VERSION 5.8 ;
BUSBITCHARS "[]" ;
DIVIDERCHAR "/" ;
UNITS
    DATABASE MICRONS 1000 ;
END UNITS

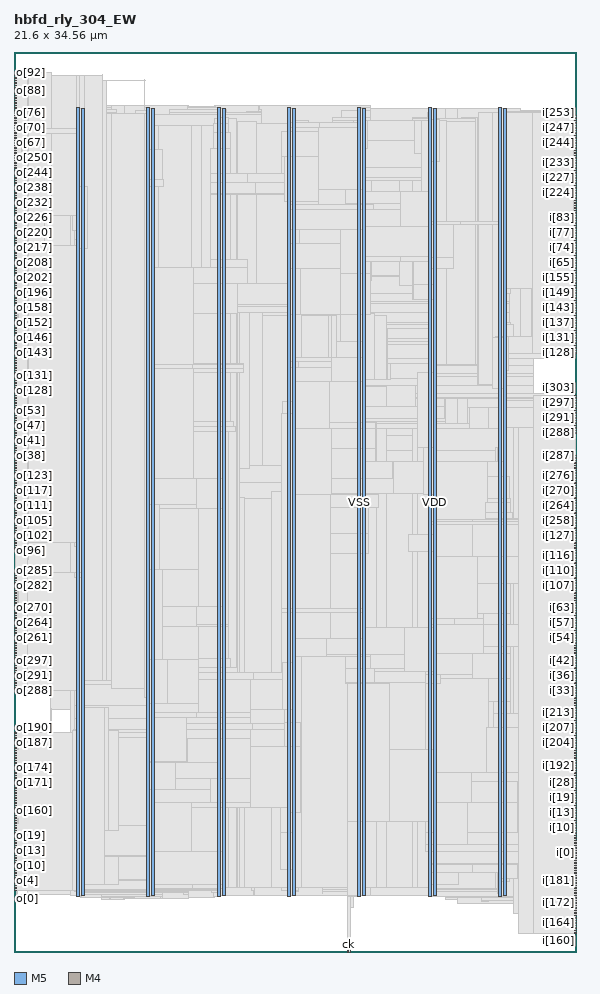
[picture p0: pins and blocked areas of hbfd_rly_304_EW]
MACRO hbfd_rly_304_EW
  FOREIGN hbfd_rly_304_EW 0 0 ;
  CLASS BLOCK ;
  SIZE 21.6 BY 34.56 ;
  PIN ck
    DIRECTION INPUT ;
    USE SIGNAL ;
    PORT
      LAYER M5 ;
        RECT  12.816 0 12.84 0.084 ;
    END
  END ck
  PIN i[0]
    DIRECTION INPUT ;
    USE SIGNAL ;
    PORT
      LAYER M4 ;
        RECT  21.516 3.792 21.6 3.816 ;
    END
  END i[0]
  PIN i[100]
    DIRECTION INPUT ;
    USE SIGNAL ;
    PORT
      LAYER M4 ;
        RECT  21.516 13.392 21.6 13.416 ;
    END
  END i[100]
  PIN i[101]
    DIRECTION INPUT ;
    USE SIGNAL ;
    PORT
      LAYER M4 ;
        RECT  21.516 13.488 21.6 13.512 ;
    END
  END i[101]
  PIN i[102]
    DIRECTION INPUT ;
    USE SIGNAL ;
    PORT
      LAYER M4 ;
        RECT  21.516 13.584 21.6 13.608 ;
    END
  END i[102]
  PIN i[103]
    DIRECTION INPUT ;
    USE SIGNAL ;
    PORT
      LAYER M4 ;
        RECT  21.516 13.68 21.6 13.704 ;
    END
  END i[103]
  PIN i[104]
    DIRECTION INPUT ;
    USE SIGNAL ;
    PORT
      LAYER M4 ;
        RECT  21.516 13.776 21.6 13.8 ;
    END
  END i[104]
  PIN i[105]
    DIRECTION INPUT ;
    USE SIGNAL ;
    PORT
      LAYER M4 ;
        RECT  21.516 13.872 21.6 13.896 ;
    END
  END i[105]
  PIN i[106]
    DIRECTION INPUT ;
    USE SIGNAL ;
    PORT
      LAYER M4 ;
        RECT  21.516 13.968 21.6 13.992 ;
    END
  END i[106]
  PIN i[107]
    DIRECTION INPUT ;
    USE SIGNAL ;
    PORT
      LAYER M4 ;
        RECT  21.516 14.064 21.6 14.088 ;
    END
  END i[107]
  PIN i[108]
    DIRECTION INPUT ;
    USE SIGNAL ;
    PORT
      LAYER M4 ;
        RECT  21.516 14.16 21.6 14.184 ;
    END
  END i[108]
  PIN i[109]
    DIRECTION INPUT ;
    USE SIGNAL ;
    PORT
      LAYER M4 ;
        RECT  21.516 14.256 21.6 14.28 ;
    END
  END i[109]
  PIN i[10]
    DIRECTION INPUT ;
    USE SIGNAL ;
    PORT
      LAYER M4 ;
        RECT  21.516 4.752 21.6 4.776 ;
    END
  END i[10]
  PIN i[110]
    DIRECTION INPUT ;
    USE SIGNAL ;
    PORT
      LAYER M4 ;
        RECT  21.516 14.352 21.6 14.376 ;
    END
  END i[110]
  PIN i[111]
    DIRECTION INPUT ;
    USE SIGNAL ;
    PORT
      LAYER M4 ;
        RECT  21.516 14.448 21.6 14.472 ;
    END
  END i[111]
  PIN i[112]
    DIRECTION INPUT ;
    USE SIGNAL ;
    PORT
      LAYER M4 ;
        RECT  21.516 14.544 21.6 14.568 ;
    END
  END i[112]
  PIN i[113]
    DIRECTION INPUT ;
    USE SIGNAL ;
    PORT
      LAYER M4 ;
        RECT  21.516 14.64 21.6 14.664 ;
    END
  END i[113]
  PIN i[114]
    DIRECTION INPUT ;
    USE SIGNAL ;
    PORT
      LAYER M4 ;
        RECT  21.516 14.736 21.6 14.76 ;
    END
  END i[114]
  PIN i[115]
    DIRECTION INPUT ;
    USE SIGNAL ;
    PORT
      LAYER M4 ;
        RECT  21.516 14.832 21.6 14.856 ;
    END
  END i[115]
  PIN i[116]
    DIRECTION INPUT ;
    USE SIGNAL ;
    PORT
      LAYER M4 ;
        RECT  21.516 14.928 21.6 14.952 ;
    END
  END i[116]
  PIN i[117]
    DIRECTION INPUT ;
    USE SIGNAL ;
    PORT
      LAYER M4 ;
        RECT  21.516 15.024 21.6 15.048 ;
    END
  END i[117]
  PIN i[118]
    DIRECTION INPUT ;
    USE SIGNAL ;
    PORT
      LAYER M4 ;
        RECT  21.516 15.12 21.6 15.144 ;
    END
  END i[118]
  PIN i[119]
    DIRECTION INPUT ;
    USE SIGNAL ;
    PORT
      LAYER M4 ;
        RECT  21.516 15.216 21.6 15.24 ;
    END
  END i[119]
  PIN i[11]
    DIRECTION INPUT ;
    USE SIGNAL ;
    PORT
      LAYER M4 ;
        RECT  21.516 4.848 21.6 4.872 ;
    END
  END i[11]
  PIN i[120]
    DIRECTION INPUT ;
    USE SIGNAL ;
    PORT
      LAYER M4 ;
        RECT  21.516 15.312 21.6 15.336 ;
    END
  END i[120]
  PIN i[121]
    DIRECTION INPUT ;
    USE SIGNAL ;
    PORT
      LAYER M4 ;
        RECT  21.516 15.408 21.6 15.432 ;
    END
  END i[121]
  PIN i[122]
    DIRECTION INPUT ;
    USE SIGNAL ;
    PORT
      LAYER M4 ;
        RECT  21.516 15.504 21.6 15.528 ;
    END
  END i[122]
  PIN i[123]
    DIRECTION INPUT ;
    USE SIGNAL ;
    PORT
      LAYER M4 ;
        RECT  21.516 15.6 21.6 15.624 ;
    END
  END i[123]
  PIN i[124]
    DIRECTION INPUT ;
    USE SIGNAL ;
    PORT
      LAYER M4 ;
        RECT  21.516 15.696 21.6 15.72 ;
    END
  END i[124]
  PIN i[125]
    DIRECTION INPUT ;
    USE SIGNAL ;
    PORT
      LAYER M4 ;
        RECT  21.516 15.792 21.6 15.816 ;
    END
  END i[125]
  PIN i[126]
    DIRECTION INPUT ;
    USE SIGNAL ;
    PORT
      LAYER M4 ;
        RECT  21.516 15.888 21.6 15.912 ;
    END
  END i[126]
  PIN i[127]
    DIRECTION INPUT ;
    USE SIGNAL ;
    PORT
      LAYER M4 ;
        RECT  21.516 15.984 21.6 16.008 ;
    END
  END i[127]
  PIN i[128]
    DIRECTION INPUT ;
    USE SIGNAL ;
    PORT
      LAYER M4 ;
        RECT  21.516 22.992 21.6 23.016 ;
    END
  END i[128]
  PIN i[129]
    DIRECTION INPUT ;
    USE SIGNAL ;
    PORT
      LAYER M4 ;
        RECT  21.516 23.088 21.6 23.112 ;
    END
  END i[129]
  PIN i[12]
    DIRECTION INPUT ;
    USE SIGNAL ;
    PORT
      LAYER M4 ;
        RECT  21.516 4.944 21.6 4.968 ;
    END
  END i[12]
  PIN i[130]
    DIRECTION INPUT ;
    USE SIGNAL ;
    PORT
      LAYER M4 ;
        RECT  21.516 23.184 21.6 23.208 ;
    END
  END i[130]
  PIN i[131]
    DIRECTION INPUT ;
    USE SIGNAL ;
    PORT
      LAYER M4 ;
        RECT  21.516 23.28 21.6 23.304 ;
    END
  END i[131]
  PIN i[132]
    DIRECTION INPUT ;
    USE SIGNAL ;
    PORT
      LAYER M4 ;
        RECT  21.516 23.376 21.6 23.4 ;
    END
  END i[132]
  PIN i[133]
    DIRECTION INPUT ;
    USE SIGNAL ;
    PORT
      LAYER M4 ;
        RECT  21.516 23.472 21.6 23.496 ;
    END
  END i[133]
  PIN i[134]
    DIRECTION INPUT ;
    USE SIGNAL ;
    PORT
      LAYER M4 ;
        RECT  21.516 23.568 21.6 23.592 ;
    END
  END i[134]
  PIN i[135]
    DIRECTION INPUT ;
    USE SIGNAL ;
    PORT
      LAYER M4 ;
        RECT  21.516 23.664 21.6 23.688 ;
    END
  END i[135]
  PIN i[136]
    DIRECTION INPUT ;
    USE SIGNAL ;
    PORT
      LAYER M4 ;
        RECT  21.516 23.76 21.6 23.784 ;
    END
  END i[136]
  PIN i[137]
    DIRECTION INPUT ;
    USE SIGNAL ;
    PORT
      LAYER M4 ;
        RECT  21.516 23.856 21.6 23.88 ;
    END
  END i[137]
  PIN i[138]
    DIRECTION INPUT ;
    USE SIGNAL ;
    PORT
      LAYER M4 ;
        RECT  21.516 23.952 21.6 23.976 ;
    END
  END i[138]
  PIN i[139]
    DIRECTION INPUT ;
    USE SIGNAL ;
    PORT
      LAYER M4 ;
        RECT  21.516 24.048 21.6 24.072 ;
    END
  END i[139]
  PIN i[13]
    DIRECTION INPUT ;
    USE SIGNAL ;
    PORT
      LAYER M4 ;
        RECT  21.516 5.04 21.6 5.064 ;
    END
  END i[13]
  PIN i[140]
    DIRECTION INPUT ;
    USE SIGNAL ;
    PORT
      LAYER M4 ;
        RECT  21.516 24.144 21.6 24.168 ;
    END
  END i[140]
  PIN i[141]
    DIRECTION INPUT ;
    USE SIGNAL ;
    PORT
      LAYER M4 ;
        RECT  21.516 24.24 21.6 24.264 ;
    END
  END i[141]
  PIN i[142]
    DIRECTION INPUT ;
    USE SIGNAL ;
    PORT
      LAYER M4 ;
        RECT  21.516 24.336 21.6 24.36 ;
    END
  END i[142]
  PIN i[143]
    DIRECTION INPUT ;
    USE SIGNAL ;
    PORT
      LAYER M4 ;
        RECT  21.516 24.432 21.6 24.456 ;
    END
  END i[143]
  PIN i[144]
    DIRECTION INPUT ;
    USE SIGNAL ;
    PORT
      LAYER M4 ;
        RECT  21.516 24.528 21.6 24.552 ;
    END
  END i[144]
  PIN i[145]
    DIRECTION INPUT ;
    USE SIGNAL ;
    PORT
      LAYER M4 ;
        RECT  21.516 24.624 21.6 24.648 ;
    END
  END i[145]
  PIN i[146]
    DIRECTION INPUT ;
    USE SIGNAL ;
    PORT
      LAYER M4 ;
        RECT  21.516 24.72 21.6 24.744 ;
    END
  END i[146]
  PIN i[147]
    DIRECTION INPUT ;
    USE SIGNAL ;
    PORT
      LAYER M4 ;
        RECT  21.516 24.816 21.6 24.84 ;
    END
  END i[147]
  PIN i[148]
    DIRECTION INPUT ;
    USE SIGNAL ;
    PORT
      LAYER M4 ;
        RECT  21.516 24.912 21.6 24.936 ;
    END
  END i[148]
  PIN i[149]
    DIRECTION INPUT ;
    USE SIGNAL ;
    PORT
      LAYER M4 ;
        RECT  21.516 25.008 21.6 25.032 ;
    END
  END i[149]
  PIN i[14]
    DIRECTION INPUT ;
    USE SIGNAL ;
    PORT
      LAYER M4 ;
        RECT  21.516 5.136 21.6 5.16 ;
    END
  END i[14]
  PIN i[150]
    DIRECTION INPUT ;
    USE SIGNAL ;
    PORT
      LAYER M4 ;
        RECT  21.516 25.104 21.6 25.128 ;
    END
  END i[150]
  PIN i[151]
    DIRECTION INPUT ;
    USE SIGNAL ;
    PORT
      LAYER M4 ;
        RECT  21.516 25.2 21.6 25.224 ;
    END
  END i[151]
  PIN i[152]
    DIRECTION INPUT ;
    USE SIGNAL ;
    PORT
      LAYER M4 ;
        RECT  21.516 25.296 21.6 25.32 ;
    END
  END i[152]
  PIN i[153]
    DIRECTION INPUT ;
    USE SIGNAL ;
    PORT
      LAYER M4 ;
        RECT  21.516 25.392 21.6 25.416 ;
    END
  END i[153]
  PIN i[154]
    DIRECTION INPUT ;
    USE SIGNAL ;
    PORT
      LAYER M4 ;
        RECT  21.516 25.488 21.6 25.512 ;
    END
  END i[154]
  PIN i[155]
    DIRECTION INPUT ;
    USE SIGNAL ;
    PORT
      LAYER M4 ;
        RECT  21.516 25.584 21.6 25.608 ;
    END
  END i[155]
  PIN i[156]
    DIRECTION INPUT ;
    USE SIGNAL ;
    PORT
      LAYER M4 ;
        RECT  21.516 25.68 21.6 25.704 ;
    END
  END i[156]
  PIN i[157]
    DIRECTION INPUT ;
    USE SIGNAL ;
    PORT
      LAYER M4 ;
        RECT  21.516 25.776 21.6 25.8 ;
    END
  END i[157]
  PIN i[158]
    DIRECTION INPUT ;
    USE SIGNAL ;
    PORT
      LAYER M4 ;
        RECT  21.516 25.872 21.6 25.896 ;
    END
  END i[158]
  PIN i[159]
    DIRECTION INPUT ;
    USE SIGNAL ;
    PORT
      LAYER M4 ;
        RECT  21.516 25.968 21.6 25.992 ;
    END
  END i[159]
  PIN i[15]
    DIRECTION INPUT ;
    USE SIGNAL ;
    PORT
      LAYER M4 ;
        RECT  21.516 5.232 21.6 5.256 ;
    END
  END i[15]
  PIN i[160]
    DIRECTION INPUT ;
    USE SIGNAL ;
    PORT
      LAYER M4 ;
        RECT  21.516 0.72 21.6 0.744 ;
    END
  END i[160]
  PIN i[161]
    DIRECTION INPUT ;
    USE SIGNAL ;
    PORT
      LAYER M4 ;
        RECT  21.516 0.816 21.6 0.84 ;
    END
  END i[161]
  PIN i[162]
    DIRECTION INPUT ;
    USE SIGNAL ;
    PORT
      LAYER M4 ;
        RECT  21.516 0.912 21.6 0.936 ;
    END
  END i[162]
  PIN i[163]
    DIRECTION INPUT ;
    USE SIGNAL ;
    PORT
      LAYER M4 ;
        RECT  21.516 1.008 21.6 1.032 ;
    END
  END i[163]
  PIN i[164]
    DIRECTION INPUT ;
    USE SIGNAL ;
    PORT
      LAYER M4 ;
        RECT  21.516 1.104 21.6 1.128 ;
    END
  END i[164]
  PIN i[165]
    DIRECTION INPUT ;
    USE SIGNAL ;
    PORT
      LAYER M4 ;
        RECT  21.516 1.2 21.6 1.224 ;
    END
  END i[165]
  PIN i[166]
    DIRECTION INPUT ;
    USE SIGNAL ;
    PORT
      LAYER M4 ;
        RECT  21.516 1.296 21.6 1.32 ;
    END
  END i[166]
  PIN i[167]
    DIRECTION INPUT ;
    USE SIGNAL ;
    PORT
      LAYER M4 ;
        RECT  21.516 1.392 21.6 1.416 ;
    END
  END i[167]
  PIN i[168]
    DIRECTION INPUT ;
    USE SIGNAL ;
    PORT
      LAYER M4 ;
        RECT  21.516 1.488 21.6 1.512 ;
    END
  END i[168]
  PIN i[169]
    DIRECTION INPUT ;
    USE SIGNAL ;
    PORT
      LAYER M4 ;
        RECT  21.516 1.584 21.6 1.608 ;
    END
  END i[169]
  PIN i[16]
    DIRECTION INPUT ;
    USE SIGNAL ;
    PORT
      LAYER M4 ;
        RECT  21.516 5.328 21.6 5.352 ;
    END
  END i[16]
  PIN i[170]
    DIRECTION INPUT ;
    USE SIGNAL ;
    PORT
      LAYER M4 ;
        RECT  21.516 1.68 21.6 1.704 ;
    END
  END i[170]
  PIN i[171]
    DIRECTION INPUT ;
    USE SIGNAL ;
    PORT
      LAYER M4 ;
        RECT  21.516 1.776 21.6 1.8 ;
    END
  END i[171]
  PIN i[172]
    DIRECTION INPUT ;
    USE SIGNAL ;
    PORT
      LAYER M4 ;
        RECT  21.516 1.872 21.6 1.896 ;
    END
  END i[172]
  PIN i[173]
    DIRECTION INPUT ;
    USE SIGNAL ;
    PORT
      LAYER M4 ;
        RECT  21.516 1.968 21.6 1.992 ;
    END
  END i[173]
  PIN i[174]
    DIRECTION INPUT ;
    USE SIGNAL ;
    PORT
      LAYER M4 ;
        RECT  21.516 2.064 21.6 2.088 ;
    END
  END i[174]
  PIN i[175]
    DIRECTION INPUT ;
    USE SIGNAL ;
    PORT
      LAYER M4 ;
        RECT  21.516 2.16 21.6 2.184 ;
    END
  END i[175]
  PIN i[176]
    DIRECTION INPUT ;
    USE SIGNAL ;
    PORT
      LAYER M4 ;
        RECT  21.516 2.256 21.6 2.28 ;
    END
  END i[176]
  PIN i[177]
    DIRECTION INPUT ;
    USE SIGNAL ;
    PORT
      LAYER M4 ;
        RECT  21.516 2.352 21.6 2.376 ;
    END
  END i[177]
  PIN i[178]
    DIRECTION INPUT ;
    USE SIGNAL ;
    PORT
      LAYER M4 ;
        RECT  21.516 2.448 21.6 2.472 ;
    END
  END i[178]
  PIN i[179]
    DIRECTION INPUT ;
    USE SIGNAL ;
    PORT
      LAYER M4 ;
        RECT  21.516 2.544 21.6 2.568 ;
    END
  END i[179]
  PIN i[17]
    DIRECTION INPUT ;
    USE SIGNAL ;
    PORT
      LAYER M4 ;
        RECT  21.516 5.424 21.6 5.448 ;
    END
  END i[17]
  PIN i[180]
    DIRECTION INPUT ;
    USE SIGNAL ;
    PORT
      LAYER M4 ;
        RECT  21.516 2.64 21.6 2.664 ;
    END
  END i[180]
  PIN i[181]
    DIRECTION INPUT ;
    USE SIGNAL ;
    PORT
      LAYER M4 ;
        RECT  21.516 2.736 21.6 2.76 ;
    END
  END i[181]
  PIN i[182]
    DIRECTION INPUT ;
    USE SIGNAL ;
    PORT
      LAYER M4 ;
        RECT  21.516 2.832 21.6 2.856 ;
    END
  END i[182]
  PIN i[183]
    DIRECTION INPUT ;
    USE SIGNAL ;
    PORT
      LAYER M4 ;
        RECT  21.516 2.928 21.6 2.952 ;
    END
  END i[183]
  PIN i[184]
    DIRECTION INPUT ;
    USE SIGNAL ;
    PORT
      LAYER M4 ;
        RECT  21.516 3.024 21.6 3.048 ;
    END
  END i[184]
  PIN i[185]
    DIRECTION INPUT ;
    USE SIGNAL ;
    PORT
      LAYER M4 ;
        RECT  21.516 3.12 21.6 3.144 ;
    END
  END i[185]
  PIN i[186]
    DIRECTION INPUT ;
    USE SIGNAL ;
    PORT
      LAYER M4 ;
        RECT  21.516 3.216 21.6 3.24 ;
    END
  END i[186]
  PIN i[187]
    DIRECTION INPUT ;
    USE SIGNAL ;
    PORT
      LAYER M4 ;
        RECT  21.516 3.312 21.6 3.336 ;
    END
  END i[187]
  PIN i[188]
    DIRECTION INPUT ;
    USE SIGNAL ;
    PORT
      LAYER M4 ;
        RECT  21.516 3.408 21.6 3.432 ;
    END
  END i[188]
  PIN i[189]
    DIRECTION INPUT ;
    USE SIGNAL ;
    PORT
      LAYER M4 ;
        RECT  21.516 3.504 21.6 3.528 ;
    END
  END i[189]
  PIN i[18]
    DIRECTION INPUT ;
    USE SIGNAL ;
    PORT
      LAYER M4 ;
        RECT  21.516 5.52 21.6 5.544 ;
    END
  END i[18]
  PIN i[190]
    DIRECTION INPUT ;
    USE SIGNAL ;
    PORT
      LAYER M4 ;
        RECT  21.516 3.6 21.6 3.624 ;
    END
  END i[190]
  PIN i[191]
    DIRECTION INPUT ;
    USE SIGNAL ;
    PORT
      LAYER M4 ;
        RECT  21.516 3.696 21.6 3.72 ;
    END
  END i[191]
  PIN i[192]
    DIRECTION INPUT ;
    USE SIGNAL ;
    PORT
      LAYER M4 ;
        RECT  21.516 6.864 21.6 6.888 ;
    END
  END i[192]
  PIN i[193]
    DIRECTION INPUT ;
    USE SIGNAL ;
    PORT
      LAYER M4 ;
        RECT  21.516 6.96 21.6 6.984 ;
    END
  END i[193]
  PIN i[194]
    DIRECTION INPUT ;
    USE SIGNAL ;
    PORT
      LAYER M4 ;
        RECT  21.516 7.056 21.6 7.08 ;
    END
  END i[194]
  PIN i[195]
    DIRECTION INPUT ;
    USE SIGNAL ;
    PORT
      LAYER M4 ;
        RECT  21.516 7.152 21.6 7.176 ;
    END
  END i[195]
  PIN i[196]
    DIRECTION INPUT ;
    USE SIGNAL ;
    PORT
      LAYER M4 ;
        RECT  21.516 7.248 21.6 7.272 ;
    END
  END i[196]
  PIN i[197]
    DIRECTION INPUT ;
    USE SIGNAL ;
    PORT
      LAYER M4 ;
        RECT  21.516 7.344 21.6 7.368 ;
    END
  END i[197]
  PIN i[198]
    DIRECTION INPUT ;
    USE SIGNAL ;
    PORT
      LAYER M4 ;
        RECT  21.516 7.44 21.6 7.464 ;
    END
  END i[198]
  PIN i[199]
    DIRECTION INPUT ;
    USE SIGNAL ;
    PORT
      LAYER M4 ;
        RECT  21.516 7.536 21.6 7.56 ;
    END
  END i[199]
  PIN i[19]
    DIRECTION INPUT ;
    USE SIGNAL ;
    PORT
      LAYER M4 ;
        RECT  21.516 5.616 21.6 5.64 ;
    END
  END i[19]
  PIN i[1]
    DIRECTION INPUT ;
    USE SIGNAL ;
    PORT
      LAYER M4 ;
        RECT  21.516 3.888 21.6 3.912 ;
    END
  END i[1]
  PIN i[200]
    DIRECTION INPUT ;
    USE SIGNAL ;
    PORT
      LAYER M4 ;
        RECT  21.516 7.632 21.6 7.656 ;
    END
  END i[200]
  PIN i[201]
    DIRECTION INPUT ;
    USE SIGNAL ;
    PORT
      LAYER M4 ;
        RECT  21.516 7.728 21.6 7.752 ;
    END
  END i[201]
  PIN i[202]
    DIRECTION INPUT ;
    USE SIGNAL ;
    PORT
      LAYER M4 ;
        RECT  21.516 7.824 21.6 7.848 ;
    END
  END i[202]
  PIN i[203]
    DIRECTION INPUT ;
    USE SIGNAL ;
    PORT
      LAYER M4 ;
        RECT  21.516 7.92 21.6 7.944 ;
    END
  END i[203]
  PIN i[204]
    DIRECTION INPUT ;
    USE SIGNAL ;
    PORT
      LAYER M4 ;
        RECT  21.516 8.016 21.6 8.04 ;
    END
  END i[204]
  PIN i[205]
    DIRECTION INPUT ;
    USE SIGNAL ;
    PORT
      LAYER M4 ;
        RECT  21.516 8.112 21.6 8.136 ;
    END
  END i[205]
  PIN i[206]
    DIRECTION INPUT ;
    USE SIGNAL ;
    PORT
      LAYER M4 ;
        RECT  21.516 8.208 21.6 8.232 ;
    END
  END i[206]
  PIN i[207]
    DIRECTION INPUT ;
    USE SIGNAL ;
    PORT
      LAYER M4 ;
        RECT  21.516 8.304 21.6 8.328 ;
    END
  END i[207]
  PIN i[208]
    DIRECTION INPUT ;
    USE SIGNAL ;
    PORT
      LAYER M4 ;
        RECT  21.516 8.4 21.6 8.424 ;
    END
  END i[208]
  PIN i[209]
    DIRECTION INPUT ;
    USE SIGNAL ;
    PORT
      LAYER M4 ;
        RECT  21.516 8.496 21.6 8.52 ;
    END
  END i[209]
  PIN i[20]
    DIRECTION INPUT ;
    USE SIGNAL ;
    PORT
      LAYER M4 ;
        RECT  21.516 5.712 21.6 5.736 ;
    END
  END i[20]
  PIN i[210]
    DIRECTION INPUT ;
    USE SIGNAL ;
    PORT
      LAYER M4 ;
        RECT  21.516 8.592 21.6 8.616 ;
    END
  END i[210]
  PIN i[211]
    DIRECTION INPUT ;
    USE SIGNAL ;
    PORT
      LAYER M4 ;
        RECT  21.516 8.688 21.6 8.712 ;
    END
  END i[211]
  PIN i[212]
    DIRECTION INPUT ;
    USE SIGNAL ;
    PORT
      LAYER M4 ;
        RECT  21.516 8.784 21.6 8.808 ;
    END
  END i[212]
  PIN i[213]
    DIRECTION INPUT ;
    USE SIGNAL ;
    PORT
      LAYER M4 ;
        RECT  21.516 8.88 21.6 8.904 ;
    END
  END i[213]
  PIN i[214]
    DIRECTION INPUT ;
    USE SIGNAL ;
    PORT
      LAYER M4 ;
        RECT  21.516 8.976 21.6 9 ;
    END
  END i[214]
  PIN i[215]
    DIRECTION INPUT ;
    USE SIGNAL ;
    PORT
      LAYER M4 ;
        RECT  21.516 9.072 21.6 9.096 ;
    END
  END i[215]
  PIN i[216]
    DIRECTION INPUT ;
    USE SIGNAL ;
    PORT
      LAYER M4 ;
        RECT  21.516 9.168 21.6 9.192 ;
    END
  END i[216]
  PIN i[217]
    DIRECTION INPUT ;
    USE SIGNAL ;
    PORT
      LAYER M4 ;
        RECT  21.516 9.264 21.6 9.288 ;
    END
  END i[217]
  PIN i[218]
    DIRECTION INPUT ;
    USE SIGNAL ;
    PORT
      LAYER M4 ;
        RECT  21.516 9.36 21.6 9.384 ;
    END
  END i[218]
  PIN i[219]
    DIRECTION INPUT ;
    USE SIGNAL ;
    PORT
      LAYER M4 ;
        RECT  21.516 9.456 21.6 9.48 ;
    END
  END i[219]
  PIN i[21]
    DIRECTION INPUT ;
    USE SIGNAL ;
    PORT
      LAYER M4 ;
        RECT  21.516 5.808 21.6 5.832 ;
    END
  END i[21]
  PIN i[220]
    DIRECTION INPUT ;
    USE SIGNAL ;
    PORT
      LAYER M4 ;
        RECT  21.516 9.552 21.6 9.576 ;
    END
  END i[220]
  PIN i[221]
    DIRECTION INPUT ;
    USE SIGNAL ;
    PORT
      LAYER M4 ;
        RECT  21.516 9.648 21.6 9.672 ;
    END
  END i[221]
  PIN i[222]
    DIRECTION INPUT ;
    USE SIGNAL ;
    PORT
      LAYER M4 ;
        RECT  21.516 9.744 21.6 9.768 ;
    END
  END i[222]
  PIN i[223]
    DIRECTION INPUT ;
    USE SIGNAL ;
    PORT
      LAYER M4 ;
        RECT  21.516 9.84 21.6 9.864 ;
    END
  END i[223]
  PIN i[224]
    DIRECTION INPUT ;
    USE SIGNAL ;
    PORT
      LAYER M4 ;
        RECT  21.516 29.136 21.6 29.16 ;
    END
  END i[224]
  PIN i[225]
    DIRECTION INPUT ;
    USE SIGNAL ;
    PORT
      LAYER M4 ;
        RECT  21.516 29.232 21.6 29.256 ;
    END
  END i[225]
  PIN i[226]
    DIRECTION INPUT ;
    USE SIGNAL ;
    PORT
      LAYER M4 ;
        RECT  21.516 29.328 21.6 29.352 ;
    END
  END i[226]
  PIN i[227]
    DIRECTION INPUT ;
    USE SIGNAL ;
    PORT
      LAYER M4 ;
        RECT  21.516 29.424 21.6 29.448 ;
    END
  END i[227]
  PIN i[228]
    DIRECTION INPUT ;
    USE SIGNAL ;
    PORT
      LAYER M4 ;
        RECT  21.516 29.52 21.6 29.544 ;
    END
  END i[228]
  PIN i[229]
    DIRECTION INPUT ;
    USE SIGNAL ;
    PORT
      LAYER M4 ;
        RECT  21.516 29.616 21.6 29.64 ;
    END
  END i[229]
  PIN i[22]
    DIRECTION INPUT ;
    USE SIGNAL ;
    PORT
      LAYER M4 ;
        RECT  21.516 5.904 21.6 5.928 ;
    END
  END i[22]
  PIN i[230]
    DIRECTION INPUT ;
    USE SIGNAL ;
    PORT
      LAYER M4 ;
        RECT  21.516 29.712 21.6 29.736 ;
    END
  END i[230]
  PIN i[231]
    DIRECTION INPUT ;
    USE SIGNAL ;
    PORT
      LAYER M4 ;
        RECT  21.516 29.808 21.6 29.832 ;
    END
  END i[231]
  PIN i[232]
    DIRECTION INPUT ;
    USE SIGNAL ;
    PORT
      LAYER M4 ;
        RECT  21.516 29.904 21.6 29.928 ;
    END
  END i[232]
  PIN i[233]
    DIRECTION INPUT ;
    USE SIGNAL ;
    PORT
      LAYER M4 ;
        RECT  21.516 30 21.6 30.024 ;
    END
  END i[233]
  PIN i[234]
    DIRECTION INPUT ;
    USE SIGNAL ;
    PORT
      LAYER M4 ;
        RECT  21.516 30.096 21.6 30.12 ;
    END
  END i[234]
  PIN i[235]
    DIRECTION INPUT ;
    USE SIGNAL ;
    PORT
      LAYER M4 ;
        RECT  21.516 30.192 21.6 30.216 ;
    END
  END i[235]
  PIN i[236]
    DIRECTION INPUT ;
    USE SIGNAL ;
    PORT
      LAYER M4 ;
        RECT  21.516 30.288 21.6 30.312 ;
    END
  END i[236]
  PIN i[237]
    DIRECTION INPUT ;
    USE SIGNAL ;
    PORT
      LAYER M4 ;
        RECT  21.516 30.384 21.6 30.408 ;
    END
  END i[237]
  PIN i[238]
    DIRECTION INPUT ;
    USE SIGNAL ;
    PORT
      LAYER M4 ;
        RECT  21.516 30.48 21.6 30.504 ;
    END
  END i[238]
  PIN i[239]
    DIRECTION INPUT ;
    USE SIGNAL ;
    PORT
      LAYER M4 ;
        RECT  21.516 30.576 21.6 30.6 ;
    END
  END i[239]
  PIN i[23]
    DIRECTION INPUT ;
    USE SIGNAL ;
    PORT
      LAYER M4 ;
        RECT  21.516 6 21.6 6.024 ;
    END
  END i[23]
  PIN i[240]
    DIRECTION INPUT ;
    USE SIGNAL ;
    PORT
      LAYER M4 ;
        RECT  21.516 30.672 21.6 30.696 ;
    END
  END i[240]
  PIN i[241]
    DIRECTION INPUT ;
    USE SIGNAL ;
    PORT
      LAYER M4 ;
        RECT  21.516 30.768 21.6 30.792 ;
    END
  END i[241]
  PIN i[242]
    DIRECTION INPUT ;
    USE SIGNAL ;
    PORT
      LAYER M4 ;
        RECT  21.516 30.864 21.6 30.888 ;
    END
  END i[242]
  PIN i[243]
    DIRECTION INPUT ;
    USE SIGNAL ;
    PORT
      LAYER M4 ;
        RECT  21.516 30.96 21.6 30.984 ;
    END
  END i[243]
  PIN i[244]
    DIRECTION INPUT ;
    USE SIGNAL ;
    PORT
      LAYER M4 ;
        RECT  21.516 31.056 21.6 31.08 ;
    END
  END i[244]
  PIN i[245]
    DIRECTION INPUT ;
    USE SIGNAL ;
    PORT
      LAYER M4 ;
        RECT  21.516 31.152 21.6 31.176 ;
    END
  END i[245]
  PIN i[246]
    DIRECTION INPUT ;
    USE SIGNAL ;
    PORT
      LAYER M4 ;
        RECT  21.516 31.248 21.6 31.272 ;
    END
  END i[246]
  PIN i[247]
    DIRECTION INPUT ;
    USE SIGNAL ;
    PORT
      LAYER M4 ;
        RECT  21.516 31.344 21.6 31.368 ;
    END
  END i[247]
  PIN i[248]
    DIRECTION INPUT ;
    USE SIGNAL ;
    PORT
      LAYER M4 ;
        RECT  21.516 31.44 21.6 31.464 ;
    END
  END i[248]
  PIN i[249]
    DIRECTION INPUT ;
    USE SIGNAL ;
    PORT
      LAYER M4 ;
        RECT  21.516 31.536 21.6 31.56 ;
    END
  END i[249]
  PIN i[24]
    DIRECTION INPUT ;
    USE SIGNAL ;
    PORT
      LAYER M4 ;
        RECT  21.516 6.096 21.6 6.12 ;
    END
  END i[24]
  PIN i[250]
    DIRECTION INPUT ;
    USE SIGNAL ;
    PORT
      LAYER M4 ;
        RECT  21.516 31.632 21.6 31.656 ;
    END
  END i[250]
  PIN i[251]
    DIRECTION INPUT ;
    USE SIGNAL ;
    PORT
      LAYER M4 ;
        RECT  21.516 31.728 21.6 31.752 ;
    END
  END i[251]
  PIN i[252]
    DIRECTION INPUT ;
    USE SIGNAL ;
    PORT
      LAYER M4 ;
        RECT  21.516 31.824 21.6 31.848 ;
    END
  END i[252]
  PIN i[253]
    DIRECTION INPUT ;
    USE SIGNAL ;
    PORT
      LAYER M4 ;
        RECT  21.516 31.92 21.6 31.944 ;
    END
  END i[253]
  PIN i[254]
    DIRECTION INPUT ;
    USE SIGNAL ;
    PORT
      LAYER M4 ;
        RECT  21.516 32.016 21.6 32.04 ;
    END
  END i[254]
  PIN i[255]
    DIRECTION INPUT ;
    USE SIGNAL ;
    PORT
      LAYER M4 ;
        RECT  21.516 32.112 21.6 32.136 ;
    END
  END i[255]
  PIN i[256]
    DIRECTION INPUT ;
    USE SIGNAL ;
    PORT
      LAYER M4 ;
        RECT  21.516 16.08 21.6 16.104 ;
    END
  END i[256]
  PIN i[257]
    DIRECTION INPUT ;
    USE SIGNAL ;
    PORT
      LAYER M4 ;
        RECT  21.516 16.176 21.6 16.2 ;
    END
  END i[257]
  PIN i[258]
    DIRECTION INPUT ;
    USE SIGNAL ;
    PORT
      LAYER M4 ;
        RECT  21.516 16.272 21.6 16.296 ;
    END
  END i[258]
  PIN i[259]
    DIRECTION INPUT ;
    USE SIGNAL ;
    PORT
      LAYER M4 ;
        RECT  21.516 16.368 21.6 16.392 ;
    END
  END i[259]
  PIN i[25]
    DIRECTION INPUT ;
    USE SIGNAL ;
    PORT
      LAYER M4 ;
        RECT  21.516 6.192 21.6 6.216 ;
    END
  END i[25]
  PIN i[260]
    DIRECTION INPUT ;
    USE SIGNAL ;
    PORT
      LAYER M4 ;
        RECT  21.516 16.464 21.6 16.488 ;
    END
  END i[260]
  PIN i[261]
    DIRECTION INPUT ;
    USE SIGNAL ;
    PORT
      LAYER M4 ;
        RECT  21.516 16.56 21.6 16.584 ;
    END
  END i[261]
  PIN i[262]
    DIRECTION INPUT ;
    USE SIGNAL ;
    PORT
      LAYER M4 ;
        RECT  21.516 16.656 21.6 16.68 ;
    END
  END i[262]
  PIN i[263]
    DIRECTION INPUT ;
    USE SIGNAL ;
    PORT
      LAYER M4 ;
        RECT  21.516 16.752 21.6 16.776 ;
    END
  END i[263]
  PIN i[264]
    DIRECTION INPUT ;
    USE SIGNAL ;
    PORT
      LAYER M4 ;
        RECT  21.516 16.848 21.6 16.872 ;
    END
  END i[264]
  PIN i[265]
    DIRECTION INPUT ;
    USE SIGNAL ;
    PORT
      LAYER M4 ;
        RECT  21.516 16.944 21.6 16.968 ;
    END
  END i[265]
  PIN i[266]
    DIRECTION INPUT ;
    USE SIGNAL ;
    PORT
      LAYER M4 ;
        RECT  21.516 17.04 21.6 17.064 ;
    END
  END i[266]
  PIN i[267]
    DIRECTION INPUT ;
    USE SIGNAL ;
    PORT
      LAYER M4 ;
        RECT  21.516 17.136 21.6 17.16 ;
    END
  END i[267]
  PIN i[268]
    DIRECTION INPUT ;
    USE SIGNAL ;
    PORT
      LAYER M4 ;
        RECT  21.516 17.232 21.6 17.256 ;
    END
  END i[268]
  PIN i[269]
    DIRECTION INPUT ;
    USE SIGNAL ;
    PORT
      LAYER M4 ;
        RECT  21.516 17.328 21.6 17.352 ;
    END
  END i[269]
  PIN i[26]
    DIRECTION INPUT ;
    USE SIGNAL ;
    PORT
      LAYER M4 ;
        RECT  21.516 6.288 21.6 6.312 ;
    END
  END i[26]
  PIN i[270]
    DIRECTION INPUT ;
    USE SIGNAL ;
    PORT
      LAYER M4 ;
        RECT  21.516 17.424 21.6 17.448 ;
    END
  END i[270]
  PIN i[271]
    DIRECTION INPUT ;
    USE SIGNAL ;
    PORT
      LAYER M4 ;
        RECT  21.516 17.52 21.6 17.544 ;
    END
  END i[271]
  PIN i[272]
    DIRECTION INPUT ;
    USE SIGNAL ;
    PORT
      LAYER M4 ;
        RECT  21.516 17.616 21.6 17.64 ;
    END
  END i[272]
  PIN i[273]
    DIRECTION INPUT ;
    USE SIGNAL ;
    PORT
      LAYER M4 ;
        RECT  21.516 17.712 21.6 17.736 ;
    END
  END i[273]
  PIN i[274]
    DIRECTION INPUT ;
    USE SIGNAL ;
    PORT
      LAYER M4 ;
        RECT  21.516 17.808 21.6 17.832 ;
    END
  END i[274]
  PIN i[275]
    DIRECTION INPUT ;
    USE SIGNAL ;
    PORT
      LAYER M4 ;
        RECT  21.516 17.904 21.6 17.928 ;
    END
  END i[275]
  PIN i[276]
    DIRECTION INPUT ;
    USE SIGNAL ;
    PORT
      LAYER M4 ;
        RECT  21.516 18 21.6 18.024 ;
    END
  END i[276]
  PIN i[277]
    DIRECTION INPUT ;
    USE SIGNAL ;
    PORT
      LAYER M4 ;
        RECT  21.516 18.096 21.6 18.12 ;
    END
  END i[277]
  PIN i[278]
    DIRECTION INPUT ;
    USE SIGNAL ;
    PORT
      LAYER M4 ;
        RECT  21.516 18.192 21.6 18.216 ;
    END
  END i[278]
  PIN i[279]
    DIRECTION INPUT ;
    USE SIGNAL ;
    PORT
      LAYER M4 ;
        RECT  21.516 18.288 21.6 18.312 ;
    END
  END i[279]
  PIN i[27]
    DIRECTION INPUT ;
    USE SIGNAL ;
    PORT
      LAYER M4 ;
        RECT  21.516 6.384 21.6 6.408 ;
    END
  END i[27]
  PIN i[280]
    DIRECTION INPUT ;
    USE SIGNAL ;
    PORT
      LAYER M4 ;
        RECT  21.516 18.384 21.6 18.408 ;
    END
  END i[280]
  PIN i[281]
    DIRECTION INPUT ;
    USE SIGNAL ;
    PORT
      LAYER M4 ;
        RECT  21.516 18.48 21.6 18.504 ;
    END
  END i[281]
  PIN i[282]
    DIRECTION INPUT ;
    USE SIGNAL ;
    PORT
      LAYER M4 ;
        RECT  21.516 18.576 21.6 18.6 ;
    END
  END i[282]
  PIN i[283]
    DIRECTION INPUT ;
    USE SIGNAL ;
    PORT
      LAYER M4 ;
        RECT  21.516 18.672 21.6 18.696 ;
    END
  END i[283]
  PIN i[284]
    DIRECTION INPUT ;
    USE SIGNAL ;
    PORT
      LAYER M4 ;
        RECT  21.516 18.768 21.6 18.792 ;
    END
  END i[284]
  PIN i[285]
    DIRECTION INPUT ;
    USE SIGNAL ;
    PORT
      LAYER M4 ;
        RECT  21.516 18.864 21.6 18.888 ;
    END
  END i[285]
  PIN i[286]
    DIRECTION INPUT ;
    USE SIGNAL ;
    PORT
      LAYER M4 ;
        RECT  21.516 18.96 21.6 18.984 ;
    END
  END i[286]
  PIN i[287]
    DIRECTION INPUT ;
    USE SIGNAL ;
    PORT
      LAYER M4 ;
        RECT  21.516 19.056 21.6 19.08 ;
    END
  END i[287]
  PIN i[288]
    DIRECTION INPUT ;
    USE SIGNAL ;
    PORT
      LAYER M4 ;
        RECT  21.516 19.92 21.6 19.944 ;
    END
  END i[288]
  PIN i[289]
    DIRECTION INPUT ;
    USE SIGNAL ;
    PORT
      LAYER M4 ;
        RECT  21.516 20.016 21.6 20.04 ;
    END
  END i[289]
  PIN i[28]
    DIRECTION INPUT ;
    USE SIGNAL ;
    PORT
      LAYER M4 ;
        RECT  21.516 6.48 21.6 6.504 ;
    END
  END i[28]
  PIN i[290]
    DIRECTION INPUT ;
    USE SIGNAL ;
    PORT
      LAYER M4 ;
        RECT  21.516 20.112 21.6 20.136 ;
    END
  END i[290]
  PIN i[291]
    DIRECTION INPUT ;
    USE SIGNAL ;
    PORT
      LAYER M4 ;
        RECT  21.516 20.208 21.6 20.232 ;
    END
  END i[291]
  PIN i[292]
    DIRECTION INPUT ;
    USE SIGNAL ;
    PORT
      LAYER M4 ;
        RECT  21.516 20.304 21.6 20.328 ;
    END
  END i[292]
  PIN i[293]
    DIRECTION INPUT ;
    USE SIGNAL ;
    PORT
      LAYER M4 ;
        RECT  21.516 20.4 21.6 20.424 ;
    END
  END i[293]
  PIN i[294]
    DIRECTION INPUT ;
    USE SIGNAL ;
    PORT
      LAYER M4 ;
        RECT  21.516 20.496 21.6 20.52 ;
    END
  END i[294]
  PIN i[295]
    DIRECTION INPUT ;
    USE SIGNAL ;
    PORT
      LAYER M4 ;
        RECT  21.516 20.592 21.6 20.616 ;
    END
  END i[295]
  PIN i[296]
    DIRECTION INPUT ;
    USE SIGNAL ;
    PORT
      LAYER M4 ;
        RECT  21.516 20.688 21.6 20.712 ;
    END
  END i[296]
  PIN i[297]
    DIRECTION INPUT ;
    USE SIGNAL ;
    PORT
      LAYER M4 ;
        RECT  21.516 20.784 21.6 20.808 ;
    END
  END i[297]
  PIN i[298]
    DIRECTION INPUT ;
    USE SIGNAL ;
    PORT
      LAYER M4 ;
        RECT  21.516 20.88 21.6 20.904 ;
    END
  END i[298]
  PIN i[299]
    DIRECTION INPUT ;
    USE SIGNAL ;
    PORT
      LAYER M4 ;
        RECT  21.516 20.976 21.6 21 ;
    END
  END i[299]
  PIN i[29]
    DIRECTION INPUT ;
    USE SIGNAL ;
    PORT
      LAYER M4 ;
        RECT  21.516 6.576 21.6 6.6 ;
    END
  END i[29]
  PIN i[2]
    DIRECTION INPUT ;
    USE SIGNAL ;
    PORT
      LAYER M4 ;
        RECT  21.516 3.984 21.6 4.008 ;
    END
  END i[2]
  PIN i[300]
    DIRECTION INPUT ;
    USE SIGNAL ;
    PORT
      LAYER M4 ;
        RECT  21.516 21.072 21.6 21.096 ;
    END
  END i[300]
  PIN i[301]
    DIRECTION INPUT ;
    USE SIGNAL ;
    PORT
      LAYER M4 ;
        RECT  21.516 21.168 21.6 21.192 ;
    END
  END i[301]
  PIN i[302]
    DIRECTION INPUT ;
    USE SIGNAL ;
    PORT
      LAYER M4 ;
        RECT  21.516 21.264 21.6 21.288 ;
    END
  END i[302]
  PIN i[303]
    DIRECTION INPUT ;
    USE SIGNAL ;
    PORT
      LAYER M4 ;
        RECT  21.516 21.36 21.6 21.384 ;
    END
  END i[303]
  PIN i[30]
    DIRECTION INPUT ;
    USE SIGNAL ;
    PORT
      LAYER M4 ;
        RECT  21.516 6.672 21.6 6.696 ;
    END
  END i[30]
  PIN i[31]
    DIRECTION INPUT ;
    USE SIGNAL ;
    PORT
      LAYER M4 ;
        RECT  21.516 6.768 21.6 6.792 ;
    END
  END i[31]
  PIN i[32]
    DIRECTION INPUT ;
    USE SIGNAL ;
    PORT
      LAYER M4 ;
        RECT  21.516 9.936 21.6 9.96 ;
    END
  END i[32]
  PIN i[33]
    DIRECTION INPUT ;
    USE SIGNAL ;
    PORT
      LAYER M4 ;
        RECT  21.516 10.032 21.6 10.056 ;
    END
  END i[33]
  PIN i[34]
    DIRECTION INPUT ;
    USE SIGNAL ;
    PORT
      LAYER M4 ;
        RECT  21.516 10.128 21.6 10.152 ;
    END
  END i[34]
  PIN i[35]
    DIRECTION INPUT ;
    USE SIGNAL ;
    PORT
      LAYER M4 ;
        RECT  21.516 10.224 21.6 10.248 ;
    END
  END i[35]
  PIN i[36]
    DIRECTION INPUT ;
    USE SIGNAL ;
    PORT
      LAYER M4 ;
        RECT  21.516 10.32 21.6 10.344 ;
    END
  END i[36]
  PIN i[37]
    DIRECTION INPUT ;
    USE SIGNAL ;
    PORT
      LAYER M4 ;
        RECT  21.516 10.416 21.6 10.44 ;
    END
  END i[37]
  PIN i[38]
    DIRECTION INPUT ;
    USE SIGNAL ;
    PORT
      LAYER M4 ;
        RECT  21.516 10.512 21.6 10.536 ;
    END
  END i[38]
  PIN i[39]
    DIRECTION INPUT ;
    USE SIGNAL ;
    PORT
      LAYER M4 ;
        RECT  21.516 10.608 21.6 10.632 ;
    END
  END i[39]
  PIN i[3]
    DIRECTION INPUT ;
    USE SIGNAL ;
    PORT
      LAYER M4 ;
        RECT  21.516 4.08 21.6 4.104 ;
    END
  END i[3]
  PIN i[40]
    DIRECTION INPUT ;
    USE SIGNAL ;
    PORT
      LAYER M4 ;
        RECT  21.516 10.704 21.6 10.728 ;
    END
  END i[40]
  PIN i[41]
    DIRECTION INPUT ;
    USE SIGNAL ;
    PORT
      LAYER M4 ;
        RECT  21.516 10.8 21.6 10.824 ;
    END
  END i[41]
  PIN i[42]
    DIRECTION INPUT ;
    USE SIGNAL ;
    PORT
      LAYER M4 ;
        RECT  21.516 10.896 21.6 10.92 ;
    END
  END i[42]
  PIN i[43]
    DIRECTION INPUT ;
    USE SIGNAL ;
    PORT
      LAYER M4 ;
        RECT  21.516 10.992 21.6 11.016 ;
    END
  END i[43]
  PIN i[44]
    DIRECTION INPUT ;
    USE SIGNAL ;
    PORT
      LAYER M4 ;
        RECT  21.516 11.088 21.6 11.112 ;
    END
  END i[44]
  PIN i[45]
    DIRECTION INPUT ;
    USE SIGNAL ;
    PORT
      LAYER M4 ;
        RECT  21.516 11.184 21.6 11.208 ;
    END
  END i[45]
  PIN i[46]
    DIRECTION INPUT ;
    USE SIGNAL ;
    PORT
      LAYER M4 ;
        RECT  21.516 11.28 21.6 11.304 ;
    END
  END i[46]
  PIN i[47]
    DIRECTION INPUT ;
    USE SIGNAL ;
    PORT
      LAYER M4 ;
        RECT  21.516 11.376 21.6 11.4 ;
    END
  END i[47]
  PIN i[48]
    DIRECTION INPUT ;
    USE SIGNAL ;
    PORT
      LAYER M4 ;
        RECT  21.516 11.472 21.6 11.496 ;
    END
  END i[48]
  PIN i[49]
    DIRECTION INPUT ;
    USE SIGNAL ;
    PORT
      LAYER M4 ;
        RECT  21.516 11.568 21.6 11.592 ;
    END
  END i[49]
  PIN i[4]
    DIRECTION INPUT ;
    USE SIGNAL ;
    PORT
      LAYER M4 ;
        RECT  21.516 4.176 21.6 4.2 ;
    END
  END i[4]
  PIN i[50]
    DIRECTION INPUT ;
    USE SIGNAL ;
    PORT
      LAYER M4 ;
        RECT  21.516 11.664 21.6 11.688 ;
    END
  END i[50]
  PIN i[51]
    DIRECTION INPUT ;
    USE SIGNAL ;
    PORT
      LAYER M4 ;
        RECT  21.516 11.76 21.6 11.784 ;
    END
  END i[51]
  PIN i[52]
    DIRECTION INPUT ;
    USE SIGNAL ;
    PORT
      LAYER M4 ;
        RECT  21.516 11.856 21.6 11.88 ;
    END
  END i[52]
  PIN i[53]
    DIRECTION INPUT ;
    USE SIGNAL ;
    PORT
      LAYER M4 ;
        RECT  21.516 11.952 21.6 11.976 ;
    END
  END i[53]
  PIN i[54]
    DIRECTION INPUT ;
    USE SIGNAL ;
    PORT
      LAYER M4 ;
        RECT  21.516 12.048 21.6 12.072 ;
    END
  END i[54]
  PIN i[55]
    DIRECTION INPUT ;
    USE SIGNAL ;
    PORT
      LAYER M4 ;
        RECT  21.516 12.144 21.6 12.168 ;
    END
  END i[55]
  PIN i[56]
    DIRECTION INPUT ;
    USE SIGNAL ;
    PORT
      LAYER M4 ;
        RECT  21.516 12.24 21.6 12.264 ;
    END
  END i[56]
  PIN i[57]
    DIRECTION INPUT ;
    USE SIGNAL ;
    PORT
      LAYER M4 ;
        RECT  21.516 12.336 21.6 12.36 ;
    END
  END i[57]
  PIN i[58]
    DIRECTION INPUT ;
    USE SIGNAL ;
    PORT
      LAYER M4 ;
        RECT  21.516 12.432 21.6 12.456 ;
    END
  END i[58]
  PIN i[59]
    DIRECTION INPUT ;
    USE SIGNAL ;
    PORT
      LAYER M4 ;
        RECT  21.516 12.528 21.6 12.552 ;
    END
  END i[59]
  PIN i[5]
    DIRECTION INPUT ;
    USE SIGNAL ;
    PORT
      LAYER M4 ;
        RECT  21.516 4.272 21.6 4.296 ;
    END
  END i[5]
  PIN i[60]
    DIRECTION INPUT ;
    USE SIGNAL ;
    PORT
      LAYER M4 ;
        RECT  21.516 12.624 21.6 12.648 ;
    END
  END i[60]
  PIN i[61]
    DIRECTION INPUT ;
    USE SIGNAL ;
    PORT
      LAYER M4 ;
        RECT  21.516 12.72 21.6 12.744 ;
    END
  END i[61]
  PIN i[62]
    DIRECTION INPUT ;
    USE SIGNAL ;
    PORT
      LAYER M4 ;
        RECT  21.516 12.816 21.6 12.84 ;
    END
  END i[62]
  PIN i[63]
    DIRECTION INPUT ;
    USE SIGNAL ;
    PORT
      LAYER M4 ;
        RECT  21.516 12.912 21.6 12.936 ;
    END
  END i[63]
  PIN i[64]
    DIRECTION INPUT ;
    USE SIGNAL ;
    PORT
      LAYER M4 ;
        RECT  21.516 26.064 21.6 26.088 ;
    END
  END i[64]
  PIN i[65]
    DIRECTION INPUT ;
    USE SIGNAL ;
    PORT
      LAYER M4 ;
        RECT  21.516 26.16 21.6 26.184 ;
    END
  END i[65]
  PIN i[66]
    DIRECTION INPUT ;
    USE SIGNAL ;
    PORT
      LAYER M4 ;
        RECT  21.516 26.256 21.6 26.28 ;
    END
  END i[66]
  PIN i[67]
    DIRECTION INPUT ;
    USE SIGNAL ;
    PORT
      LAYER M4 ;
        RECT  21.516 26.352 21.6 26.376 ;
    END
  END i[67]
  PIN i[68]
    DIRECTION INPUT ;
    USE SIGNAL ;
    PORT
      LAYER M4 ;
        RECT  21.516 26.448 21.6 26.472 ;
    END
  END i[68]
  PIN i[69]
    DIRECTION INPUT ;
    USE SIGNAL ;
    PORT
      LAYER M4 ;
        RECT  21.516 26.544 21.6 26.568 ;
    END
  END i[69]
  PIN i[6]
    DIRECTION INPUT ;
    USE SIGNAL ;
    PORT
      LAYER M4 ;
        RECT  21.516 4.368 21.6 4.392 ;
    END
  END i[6]
  PIN i[70]
    DIRECTION INPUT ;
    USE SIGNAL ;
    PORT
      LAYER M4 ;
        RECT  21.516 26.64 21.6 26.664 ;
    END
  END i[70]
  PIN i[71]
    DIRECTION INPUT ;
    USE SIGNAL ;
    PORT
      LAYER M4 ;
        RECT  21.516 26.736 21.6 26.76 ;
    END
  END i[71]
  PIN i[72]
    DIRECTION INPUT ;
    USE SIGNAL ;
    PORT
      LAYER M4 ;
        RECT  21.516 26.832 21.6 26.856 ;
    END
  END i[72]
  PIN i[73]
    DIRECTION INPUT ;
    USE SIGNAL ;
    PORT
      LAYER M4 ;
        RECT  21.516 26.928 21.6 26.952 ;
    END
  END i[73]
  PIN i[74]
    DIRECTION INPUT ;
    USE SIGNAL ;
    PORT
      LAYER M4 ;
        RECT  21.516 27.024 21.6 27.048 ;
    END
  END i[74]
  PIN i[75]
    DIRECTION INPUT ;
    USE SIGNAL ;
    PORT
      LAYER M4 ;
        RECT  21.516 27.12 21.6 27.144 ;
    END
  END i[75]
  PIN i[76]
    DIRECTION INPUT ;
    USE SIGNAL ;
    PORT
      LAYER M4 ;
        RECT  21.516 27.216 21.6 27.24 ;
    END
  END i[76]
  PIN i[77]
    DIRECTION INPUT ;
    USE SIGNAL ;
    PORT
      LAYER M4 ;
        RECT  21.516 27.312 21.6 27.336 ;
    END
  END i[77]
  PIN i[78]
    DIRECTION INPUT ;
    USE SIGNAL ;
    PORT
      LAYER M4 ;
        RECT  21.516 27.408 21.6 27.432 ;
    END
  END i[78]
  PIN i[79]
    DIRECTION INPUT ;
    USE SIGNAL ;
    PORT
      LAYER M4 ;
        RECT  21.516 27.504 21.6 27.528 ;
    END
  END i[79]
  PIN i[7]
    DIRECTION INPUT ;
    USE SIGNAL ;
    PORT
      LAYER M4 ;
        RECT  21.516 4.464 21.6 4.488 ;
    END
  END i[7]
  PIN i[80]
    DIRECTION INPUT ;
    USE SIGNAL ;
    PORT
      LAYER M4 ;
        RECT  21.516 27.6 21.6 27.624 ;
    END
  END i[80]
  PIN i[81]
    DIRECTION INPUT ;
    USE SIGNAL ;
    PORT
      LAYER M4 ;
        RECT  21.516 27.696 21.6 27.72 ;
    END
  END i[81]
  PIN i[82]
    DIRECTION INPUT ;
    USE SIGNAL ;
    PORT
      LAYER M4 ;
        RECT  21.516 27.792 21.6 27.816 ;
    END
  END i[82]
  PIN i[83]
    DIRECTION INPUT ;
    USE SIGNAL ;
    PORT
      LAYER M4 ;
        RECT  21.516 27.888 21.6 27.912 ;
    END
  END i[83]
  PIN i[84]
    DIRECTION INPUT ;
    USE SIGNAL ;
    PORT
      LAYER M4 ;
        RECT  21.516 27.984 21.6 28.008 ;
    END
  END i[84]
  PIN i[85]
    DIRECTION INPUT ;
    USE SIGNAL ;
    PORT
      LAYER M4 ;
        RECT  21.516 28.08 21.6 28.104 ;
    END
  END i[85]
  PIN i[86]
    DIRECTION INPUT ;
    USE SIGNAL ;
    PORT
      LAYER M4 ;
        RECT  21.516 28.176 21.6 28.2 ;
    END
  END i[86]
  PIN i[87]
    DIRECTION INPUT ;
    USE SIGNAL ;
    PORT
      LAYER M4 ;
        RECT  21.516 28.272 21.6 28.296 ;
    END
  END i[87]
  PIN i[88]
    DIRECTION INPUT ;
    USE SIGNAL ;
    PORT
      LAYER M4 ;
        RECT  21.516 28.368 21.6 28.392 ;
    END
  END i[88]
  PIN i[89]
    DIRECTION INPUT ;
    USE SIGNAL ;
    PORT
      LAYER M4 ;
        RECT  21.516 28.464 21.6 28.488 ;
    END
  END i[89]
  PIN i[8]
    DIRECTION INPUT ;
    USE SIGNAL ;
    PORT
      LAYER M4 ;
        RECT  21.516 4.56 21.6 4.584 ;
    END
  END i[8]
  PIN i[90]
    DIRECTION INPUT ;
    USE SIGNAL ;
    PORT
      LAYER M4 ;
        RECT  21.516 28.56 21.6 28.584 ;
    END
  END i[90]
  PIN i[91]
    DIRECTION INPUT ;
    USE SIGNAL ;
    PORT
      LAYER M4 ;
        RECT  21.516 28.656 21.6 28.68 ;
    END
  END i[91]
  PIN i[92]
    DIRECTION INPUT ;
    USE SIGNAL ;
    PORT
      LAYER M4 ;
        RECT  21.516 28.752 21.6 28.776 ;
    END
  END i[92]
  PIN i[93]
    DIRECTION INPUT ;
    USE SIGNAL ;
    PORT
      LAYER M4 ;
        RECT  21.516 28.848 21.6 28.872 ;
    END
  END i[93]
  PIN i[94]
    DIRECTION INPUT ;
    USE SIGNAL ;
    PORT
      LAYER M4 ;
        RECT  21.516 28.944 21.6 28.968 ;
    END
  END i[94]
  PIN i[95]
    DIRECTION INPUT ;
    USE SIGNAL ;
    PORT
      LAYER M4 ;
        RECT  21.516 29.04 21.6 29.064 ;
    END
  END i[95]
  PIN i[96]
    DIRECTION INPUT ;
    USE SIGNAL ;
    PORT
      LAYER M4 ;
        RECT  21.516 13.008 21.6 13.032 ;
    END
  END i[96]
  PIN i[97]
    DIRECTION INPUT ;
    USE SIGNAL ;
    PORT
      LAYER M4 ;
        RECT  21.516 13.104 21.6 13.128 ;
    END
  END i[97]
  PIN i[98]
    DIRECTION INPUT ;
    USE SIGNAL ;
    PORT
      LAYER M4 ;
        RECT  21.516 13.2 21.6 13.224 ;
    END
  END i[98]
  PIN i[99]
    DIRECTION INPUT ;
    USE SIGNAL ;
    PORT
      LAYER M4 ;
        RECT  21.516 13.296 21.6 13.32 ;
    END
  END i[99]
  PIN i[9]
    DIRECTION INPUT ;
    USE SIGNAL ;
    PORT
      LAYER M4 ;
        RECT  21.516 4.656 21.6 4.68 ;
    END
  END i[9]
  PIN o[0]
    DIRECTION OUTPUT ;
    USE SIGNAL ;
    PORT
      LAYER M4 ;
        RECT  0 2.352 0.084 2.376 ;
    END
  END o[0]
  PIN o[100]
    DIRECTION OUTPUT ;
    USE SIGNAL ;
    PORT
      LAYER M4 ;
        RECT  0 15.792 0.084 15.816 ;
    END
  END o[100]
  PIN o[101]
    DIRECTION OUTPUT ;
    USE SIGNAL ;
    PORT
      LAYER M4 ;
        RECT  0 15.888 0.084 15.912 ;
    END
  END o[101]
  PIN o[102]
    DIRECTION OUTPUT ;
    USE SIGNAL ;
    PORT
      LAYER M4 ;
        RECT  0 15.984 0.084 16.008 ;
    END
  END o[102]
  PIN o[103]
    DIRECTION OUTPUT ;
    USE SIGNAL ;
    PORT
      LAYER M4 ;
        RECT  0 16.08 0.084 16.104 ;
    END
  END o[103]
  PIN o[104]
    DIRECTION OUTPUT ;
    USE SIGNAL ;
    PORT
      LAYER M4 ;
        RECT  0 16.176 0.084 16.2 ;
    END
  END o[104]
  PIN o[105]
    DIRECTION OUTPUT ;
    USE SIGNAL ;
    PORT
      LAYER M4 ;
        RECT  0 16.272 0.084 16.296 ;
    END
  END o[105]
  PIN o[106]
    DIRECTION OUTPUT ;
    USE SIGNAL ;
    PORT
      LAYER M4 ;
        RECT  0 16.368 0.084 16.392 ;
    END
  END o[106]
  PIN o[107]
    DIRECTION OUTPUT ;
    USE SIGNAL ;
    PORT
      LAYER M4 ;
        RECT  0 16.464 0.084 16.488 ;
    END
  END o[107]
  PIN o[108]
    DIRECTION OUTPUT ;
    USE SIGNAL ;
    PORT
      LAYER M4 ;
        RECT  0 16.56 0.084 16.584 ;
    END
  END o[108]
  PIN o[109]
    DIRECTION OUTPUT ;
    USE SIGNAL ;
    PORT
      LAYER M4 ;
        RECT  0 16.656 0.084 16.68 ;
    END
  END o[109]
  PIN o[10]
    DIRECTION OUTPUT ;
    USE SIGNAL ;
    PORT
      LAYER M4 ;
        RECT  0 3.312 0.084 3.336 ;
    END
  END o[10]
  PIN o[110]
    DIRECTION OUTPUT ;
    USE SIGNAL ;
    PORT
      LAYER M4 ;
        RECT  0 16.752 0.084 16.776 ;
    END
  END o[110]
  PIN o[111]
    DIRECTION OUTPUT ;
    USE SIGNAL ;
    PORT
      LAYER M4 ;
        RECT  0 16.848 0.084 16.872 ;
    END
  END o[111]
  PIN o[112]
    DIRECTION OUTPUT ;
    USE SIGNAL ;
    PORT
      LAYER M4 ;
        RECT  0 16.944 0.084 16.968 ;
    END
  END o[112]
  PIN o[113]
    DIRECTION OUTPUT ;
    USE SIGNAL ;
    PORT
      LAYER M4 ;
        RECT  0 17.04 0.084 17.064 ;
    END
  END o[113]
  PIN o[114]
    DIRECTION OUTPUT ;
    USE SIGNAL ;
    PORT
      LAYER M4 ;
        RECT  0 17.136 0.084 17.16 ;
    END
  END o[114]
  PIN o[115]
    DIRECTION OUTPUT ;
    USE SIGNAL ;
    PORT
      LAYER M4 ;
        RECT  0 17.232 0.084 17.256 ;
    END
  END o[115]
  PIN o[116]
    DIRECTION OUTPUT ;
    USE SIGNAL ;
    PORT
      LAYER M4 ;
        RECT  0 17.328 0.084 17.352 ;
    END
  END o[116]
  PIN o[117]
    DIRECTION OUTPUT ;
    USE SIGNAL ;
    PORT
      LAYER M4 ;
        RECT  0 17.424 0.084 17.448 ;
    END
  END o[117]
  PIN o[118]
    DIRECTION OUTPUT ;
    USE SIGNAL ;
    PORT
      LAYER M4 ;
        RECT  0 17.52 0.084 17.544 ;
    END
  END o[118]
  PIN o[119]
    DIRECTION OUTPUT ;
    USE SIGNAL ;
    PORT
      LAYER M4 ;
        RECT  0 17.616 0.084 17.64 ;
    END
  END o[119]
  PIN o[11]
    DIRECTION OUTPUT ;
    USE SIGNAL ;
    PORT
      LAYER M4 ;
        RECT  0 3.408 0.084 3.432 ;
    END
  END o[11]
  PIN o[120]
    DIRECTION OUTPUT ;
    USE SIGNAL ;
    PORT
      LAYER M4 ;
        RECT  0 17.712 0.084 17.736 ;
    END
  END o[120]
  PIN o[121]
    DIRECTION OUTPUT ;
    USE SIGNAL ;
    PORT
      LAYER M4 ;
        RECT  0 17.808 0.084 17.832 ;
    END
  END o[121]
  PIN o[122]
    DIRECTION OUTPUT ;
    USE SIGNAL ;
    PORT
      LAYER M4 ;
        RECT  0 17.904 0.084 17.928 ;
    END
  END o[122]
  PIN o[123]
    DIRECTION OUTPUT ;
    USE SIGNAL ;
    PORT
      LAYER M4 ;
        RECT  0 18 0.084 18.024 ;
    END
  END o[123]
  PIN o[124]
    DIRECTION OUTPUT ;
    USE SIGNAL ;
    PORT
      LAYER M4 ;
        RECT  0 18.096 0.084 18.12 ;
    END
  END o[124]
  PIN o[125]
    DIRECTION OUTPUT ;
    USE SIGNAL ;
    PORT
      LAYER M4 ;
        RECT  0 18.192 0.084 18.216 ;
    END
  END o[125]
  PIN o[126]
    DIRECTION OUTPUT ;
    USE SIGNAL ;
    PORT
      LAYER M4 ;
        RECT  0 18.288 0.084 18.312 ;
    END
  END o[126]
  PIN o[127]
    DIRECTION OUTPUT ;
    USE SIGNAL ;
    PORT
      LAYER M4 ;
        RECT  0 18.384 0.084 18.408 ;
    END
  END o[127]
  PIN o[128]
    DIRECTION OUTPUT ;
    USE SIGNAL ;
    PORT
      LAYER M4 ;
        RECT  0 21.552 0.084 21.576 ;
    END
  END o[128]
  PIN o[129]
    DIRECTION OUTPUT ;
    USE SIGNAL ;
    PORT
      LAYER M4 ;
        RECT  0 21.648 0.084 21.672 ;
    END
  END o[129]
  PIN o[12]
    DIRECTION OUTPUT ;
    USE SIGNAL ;
    PORT
      LAYER M4 ;
        RECT  0 3.504 0.084 3.528 ;
    END
  END o[12]
  PIN o[130]
    DIRECTION OUTPUT ;
    USE SIGNAL ;
    PORT
      LAYER M4 ;
        RECT  0 21.744 0.084 21.768 ;
    END
  END o[130]
  PIN o[131]
    DIRECTION OUTPUT ;
    USE SIGNAL ;
    PORT
      LAYER M4 ;
        RECT  0 21.84 0.084 21.864 ;
    END
  END o[131]
  PIN o[132]
    DIRECTION OUTPUT ;
    USE SIGNAL ;
    PORT
      LAYER M4 ;
        RECT  0 21.936 0.084 21.96 ;
    END
  END o[132]
  PIN o[133]
    DIRECTION OUTPUT ;
    USE SIGNAL ;
    PORT
      LAYER M4 ;
        RECT  0 22.032 0.084 22.056 ;
    END
  END o[133]
  PIN o[134]
    DIRECTION OUTPUT ;
    USE SIGNAL ;
    PORT
      LAYER M4 ;
        RECT  0 22.128 0.084 22.152 ;
    END
  END o[134]
  PIN o[135]
    DIRECTION OUTPUT ;
    USE SIGNAL ;
    PORT
      LAYER M4 ;
        RECT  0 22.224 0.084 22.248 ;
    END
  END o[135]
  PIN o[136]
    DIRECTION OUTPUT ;
    USE SIGNAL ;
    PORT
      LAYER M4 ;
        RECT  0 22.32 0.084 22.344 ;
    END
  END o[136]
  PIN o[137]
    DIRECTION OUTPUT ;
    USE SIGNAL ;
    PORT
      LAYER M4 ;
        RECT  0 22.416 0.084 22.44 ;
    END
  END o[137]
  PIN o[138]
    DIRECTION OUTPUT ;
    USE SIGNAL ;
    PORT
      LAYER M4 ;
        RECT  0 22.512 0.084 22.536 ;
    END
  END o[138]
  PIN o[139]
    DIRECTION OUTPUT ;
    USE SIGNAL ;
    PORT
      LAYER M4 ;
        RECT  0 22.608 0.084 22.632 ;
    END
  END o[139]
  PIN o[13]
    DIRECTION OUTPUT ;
    USE SIGNAL ;
    PORT
      LAYER M4 ;
        RECT  0 3.6 0.084 3.624 ;
    END
  END o[13]
  PIN o[140]
    DIRECTION OUTPUT ;
    USE SIGNAL ;
    PORT
      LAYER M4 ;
        RECT  0 22.704 0.084 22.728 ;
    END
  END o[140]
  PIN o[141]
    DIRECTION OUTPUT ;
    USE SIGNAL ;
    PORT
      LAYER M4 ;
        RECT  0 22.8 0.084 22.824 ;
    END
  END o[141]
  PIN o[142]
    DIRECTION OUTPUT ;
    USE SIGNAL ;
    PORT
      LAYER M4 ;
        RECT  0 22.896 0.084 22.92 ;
    END
  END o[142]
  PIN o[143]
    DIRECTION OUTPUT ;
    USE SIGNAL ;
    PORT
      LAYER M4 ;
        RECT  0 22.992 0.084 23.016 ;
    END
  END o[143]
  PIN o[144]
    DIRECTION OUTPUT ;
    USE SIGNAL ;
    PORT
      LAYER M4 ;
        RECT  0 23.088 0.084 23.112 ;
    END
  END o[144]
  PIN o[145]
    DIRECTION OUTPUT ;
    USE SIGNAL ;
    PORT
      LAYER M4 ;
        RECT  0 23.184 0.084 23.208 ;
    END
  END o[145]
  PIN o[146]
    DIRECTION OUTPUT ;
    USE SIGNAL ;
    PORT
      LAYER M4 ;
        RECT  0 23.28 0.084 23.304 ;
    END
  END o[146]
  PIN o[147]
    DIRECTION OUTPUT ;
    USE SIGNAL ;
    PORT
      LAYER M4 ;
        RECT  0 23.376 0.084 23.4 ;
    END
  END o[147]
  PIN o[148]
    DIRECTION OUTPUT ;
    USE SIGNAL ;
    PORT
      LAYER M4 ;
        RECT  0 23.472 0.084 23.496 ;
    END
  END o[148]
  PIN o[149]
    DIRECTION OUTPUT ;
    USE SIGNAL ;
    PORT
      LAYER M4 ;
        RECT  0 23.568 0.084 23.592 ;
    END
  END o[149]
  PIN o[14]
    DIRECTION OUTPUT ;
    USE SIGNAL ;
    PORT
      LAYER M4 ;
        RECT  0 3.696 0.084 3.72 ;
    END
  END o[14]
  PIN o[150]
    DIRECTION OUTPUT ;
    USE SIGNAL ;
    PORT
      LAYER M4 ;
        RECT  0 23.664 0.084 23.688 ;
    END
  END o[150]
  PIN o[151]
    DIRECTION OUTPUT ;
    USE SIGNAL ;
    PORT
      LAYER M4 ;
        RECT  0 23.76 0.084 23.784 ;
    END
  END o[151]
  PIN o[152]
    DIRECTION OUTPUT ;
    USE SIGNAL ;
    PORT
      LAYER M4 ;
        RECT  0 23.856 0.084 23.88 ;
    END
  END o[152]
  PIN o[153]
    DIRECTION OUTPUT ;
    USE SIGNAL ;
    PORT
      LAYER M4 ;
        RECT  0 23.952 0.084 23.976 ;
    END
  END o[153]
  PIN o[154]
    DIRECTION OUTPUT ;
    USE SIGNAL ;
    PORT
      LAYER M4 ;
        RECT  0 24.048 0.084 24.072 ;
    END
  END o[154]
  PIN o[155]
    DIRECTION OUTPUT ;
    USE SIGNAL ;
    PORT
      LAYER M4 ;
        RECT  0 24.144 0.084 24.168 ;
    END
  END o[155]
  PIN o[156]
    DIRECTION OUTPUT ;
    USE SIGNAL ;
    PORT
      LAYER M4 ;
        RECT  0 24.24 0.084 24.264 ;
    END
  END o[156]
  PIN o[157]
    DIRECTION OUTPUT ;
    USE SIGNAL ;
    PORT
      LAYER M4 ;
        RECT  0 24.336 0.084 24.36 ;
    END
  END o[157]
  PIN o[158]
    DIRECTION OUTPUT ;
    USE SIGNAL ;
    PORT
      LAYER M4 ;
        RECT  0 24.432 0.084 24.456 ;
    END
  END o[158]
  PIN o[159]
    DIRECTION OUTPUT ;
    USE SIGNAL ;
    PORT
      LAYER M4 ;
        RECT  0 24.528 0.084 24.552 ;
    END
  END o[159]
  PIN o[15]
    DIRECTION OUTPUT ;
    USE SIGNAL ;
    PORT
      LAYER M4 ;
        RECT  0 3.792 0.084 3.816 ;
    END
  END o[15]
  PIN o[160]
    DIRECTION OUTPUT ;
    USE SIGNAL ;
    PORT
      LAYER M4 ;
        RECT  0 5.424 0.084 5.448 ;
    END
  END o[160]
  PIN o[161]
    DIRECTION OUTPUT ;
    USE SIGNAL ;
    PORT
      LAYER M4 ;
        RECT  0 5.52 0.084 5.544 ;
    END
  END o[161]
  PIN o[162]
    DIRECTION OUTPUT ;
    USE SIGNAL ;
    PORT
      LAYER M4 ;
        RECT  0 5.616 0.084 5.64 ;
    END
  END o[162]
  PIN o[163]
    DIRECTION OUTPUT ;
    USE SIGNAL ;
    PORT
      LAYER M4 ;
        RECT  0 5.712 0.084 5.736 ;
    END
  END o[163]
  PIN o[164]
    DIRECTION OUTPUT ;
    USE SIGNAL ;
    PORT
      LAYER M4 ;
        RECT  0 5.808 0.084 5.832 ;
    END
  END o[164]
  PIN o[165]
    DIRECTION OUTPUT ;
    USE SIGNAL ;
    PORT
      LAYER M4 ;
        RECT  0 5.904 0.084 5.928 ;
    END
  END o[165]
  PIN o[166]
    DIRECTION OUTPUT ;
    USE SIGNAL ;
    PORT
      LAYER M4 ;
        RECT  0 6 0.084 6.024 ;
    END
  END o[166]
  PIN o[167]
    DIRECTION OUTPUT ;
    USE SIGNAL ;
    PORT
      LAYER M4 ;
        RECT  0 6.096 0.084 6.12 ;
    END
  END o[167]
  PIN o[168]
    DIRECTION OUTPUT ;
    USE SIGNAL ;
    PORT
      LAYER M4 ;
        RECT  0 6.192 0.084 6.216 ;
    END
  END o[168]
  PIN o[169]
    DIRECTION OUTPUT ;
    USE SIGNAL ;
    PORT
      LAYER M4 ;
        RECT  0 6.288 0.084 6.312 ;
    END
  END o[169]
  PIN o[16]
    DIRECTION OUTPUT ;
    USE SIGNAL ;
    PORT
      LAYER M4 ;
        RECT  0 3.888 0.084 3.912 ;
    END
  END o[16]
  PIN o[170]
    DIRECTION OUTPUT ;
    USE SIGNAL ;
    PORT
      LAYER M4 ;
        RECT  0 6.384 0.084 6.408 ;
    END
  END o[170]
  PIN o[171]
    DIRECTION OUTPUT ;
    USE SIGNAL ;
    PORT
      LAYER M4 ;
        RECT  0 6.48 0.084 6.504 ;
    END
  END o[171]
  PIN o[172]
    DIRECTION OUTPUT ;
    USE SIGNAL ;
    PORT
      LAYER M4 ;
        RECT  0 6.576 0.084 6.6 ;
    END
  END o[172]
  PIN o[173]
    DIRECTION OUTPUT ;
    USE SIGNAL ;
    PORT
      LAYER M4 ;
        RECT  0 6.672 0.084 6.696 ;
    END
  END o[173]
  PIN o[174]
    DIRECTION OUTPUT ;
    USE SIGNAL ;
    PORT
      LAYER M4 ;
        RECT  0 6.768 0.084 6.792 ;
    END
  END o[174]
  PIN o[175]
    DIRECTION OUTPUT ;
    USE SIGNAL ;
    PORT
      LAYER M4 ;
        RECT  0 6.864 0.084 6.888 ;
    END
  END o[175]
  PIN o[176]
    DIRECTION OUTPUT ;
    USE SIGNAL ;
    PORT
      LAYER M4 ;
        RECT  0 6.96 0.084 6.984 ;
    END
  END o[176]
  PIN o[177]
    DIRECTION OUTPUT ;
    USE SIGNAL ;
    PORT
      LAYER M4 ;
        RECT  0 7.056 0.084 7.08 ;
    END
  END o[177]
  PIN o[178]
    DIRECTION OUTPUT ;
    USE SIGNAL ;
    PORT
      LAYER M4 ;
        RECT  0 7.152 0.084 7.176 ;
    END
  END o[178]
  PIN o[179]
    DIRECTION OUTPUT ;
    USE SIGNAL ;
    PORT
      LAYER M4 ;
        RECT  0 7.248 0.084 7.272 ;
    END
  END o[179]
  PIN o[17]
    DIRECTION OUTPUT ;
    USE SIGNAL ;
    PORT
      LAYER M4 ;
        RECT  0 3.984 0.084 4.008 ;
    END
  END o[17]
  PIN o[180]
    DIRECTION OUTPUT ;
    USE SIGNAL ;
    PORT
      LAYER M4 ;
        RECT  0 7.344 0.084 7.368 ;
    END
  END o[180]
  PIN o[181]
    DIRECTION OUTPUT ;
    USE SIGNAL ;
    PORT
      LAYER M4 ;
        RECT  0 7.44 0.084 7.464 ;
    END
  END o[181]
  PIN o[182]
    DIRECTION OUTPUT ;
    USE SIGNAL ;
    PORT
      LAYER M4 ;
        RECT  0 7.536 0.084 7.56 ;
    END
  END o[182]
  PIN o[183]
    DIRECTION OUTPUT ;
    USE SIGNAL ;
    PORT
      LAYER M4 ;
        RECT  0 7.632 0.084 7.656 ;
    END
  END o[183]
  PIN o[184]
    DIRECTION OUTPUT ;
    USE SIGNAL ;
    PORT
      LAYER M4 ;
        RECT  0 7.728 0.084 7.752 ;
    END
  END o[184]
  PIN o[185]
    DIRECTION OUTPUT ;
    USE SIGNAL ;
    PORT
      LAYER M4 ;
        RECT  0 7.824 0.084 7.848 ;
    END
  END o[185]
  PIN o[186]
    DIRECTION OUTPUT ;
    USE SIGNAL ;
    PORT
      LAYER M4 ;
        RECT  0 7.92 0.084 7.944 ;
    END
  END o[186]
  PIN o[187]
    DIRECTION OUTPUT ;
    USE SIGNAL ;
    PORT
      LAYER M4 ;
        RECT  0 8.016 0.084 8.04 ;
    END
  END o[187]
  PIN o[188]
    DIRECTION OUTPUT ;
    USE SIGNAL ;
    PORT
      LAYER M4 ;
        RECT  0 8.112 0.084 8.136 ;
    END
  END o[188]
  PIN o[189]
    DIRECTION OUTPUT ;
    USE SIGNAL ;
    PORT
      LAYER M4 ;
        RECT  0 8.208 0.084 8.232 ;
    END
  END o[189]
  PIN o[18]
    DIRECTION OUTPUT ;
    USE SIGNAL ;
    PORT
      LAYER M4 ;
        RECT  0 4.08 0.084 4.104 ;
    END
  END o[18]
  PIN o[190]
    DIRECTION OUTPUT ;
    USE SIGNAL ;
    PORT
      LAYER M4 ;
        RECT  0 8.304 0.084 8.328 ;
    END
  END o[190]
  PIN o[191]
    DIRECTION OUTPUT ;
    USE SIGNAL ;
    PORT
      LAYER M4 ;
        RECT  0 8.4 0.084 8.424 ;
    END
  END o[191]
  PIN o[192]
    DIRECTION OUTPUT ;
    USE SIGNAL ;
    PORT
      LAYER M4 ;
        RECT  0 24.624 0.084 24.648 ;
    END
  END o[192]
  PIN o[193]
    DIRECTION OUTPUT ;
    USE SIGNAL ;
    PORT
      LAYER M4 ;
        RECT  0 24.72 0.084 24.744 ;
    END
  END o[193]
  PIN o[194]
    DIRECTION OUTPUT ;
    USE SIGNAL ;
    PORT
      LAYER M4 ;
        RECT  0 24.816 0.084 24.84 ;
    END
  END o[194]
  PIN o[195]
    DIRECTION OUTPUT ;
    USE SIGNAL ;
    PORT
      LAYER M4 ;
        RECT  0 24.912 0.084 24.936 ;
    END
  END o[195]
  PIN o[196]
    DIRECTION OUTPUT ;
    USE SIGNAL ;
    PORT
      LAYER M4 ;
        RECT  0 25.008 0.084 25.032 ;
    END
  END o[196]
  PIN o[197]
    DIRECTION OUTPUT ;
    USE SIGNAL ;
    PORT
      LAYER M4 ;
        RECT  0 25.104 0.084 25.128 ;
    END
  END o[197]
  PIN o[198]
    DIRECTION OUTPUT ;
    USE SIGNAL ;
    PORT
      LAYER M4 ;
        RECT  0 25.2 0.084 25.224 ;
    END
  END o[198]
  PIN o[199]
    DIRECTION OUTPUT ;
    USE SIGNAL ;
    PORT
      LAYER M4 ;
        RECT  0 25.296 0.084 25.32 ;
    END
  END o[199]
  PIN o[19]
    DIRECTION OUTPUT ;
    USE SIGNAL ;
    PORT
      LAYER M4 ;
        RECT  0 4.176 0.084 4.2 ;
    END
  END o[19]
  PIN o[1]
    DIRECTION OUTPUT ;
    USE SIGNAL ;
    PORT
      LAYER M4 ;
        RECT  0 2.448 0.084 2.472 ;
    END
  END o[1]
  PIN o[200]
    DIRECTION OUTPUT ;
    USE SIGNAL ;
    PORT
      LAYER M4 ;
        RECT  0 25.392 0.084 25.416 ;
    END
  END o[200]
  PIN o[201]
    DIRECTION OUTPUT ;
    USE SIGNAL ;
    PORT
      LAYER M4 ;
        RECT  0 25.488 0.084 25.512 ;
    END
  END o[201]
  PIN o[202]
    DIRECTION OUTPUT ;
    USE SIGNAL ;
    PORT
      LAYER M4 ;
        RECT  0 25.584 0.084 25.608 ;
    END
  END o[202]
  PIN o[203]
    DIRECTION OUTPUT ;
    USE SIGNAL ;
    PORT
      LAYER M4 ;
        RECT  0 25.68 0.084 25.704 ;
    END
  END o[203]
  PIN o[204]
    DIRECTION OUTPUT ;
    USE SIGNAL ;
    PORT
      LAYER M4 ;
        RECT  0 25.776 0.084 25.8 ;
    END
  END o[204]
  PIN o[205]
    DIRECTION OUTPUT ;
    USE SIGNAL ;
    PORT
      LAYER M4 ;
        RECT  0 25.872 0.084 25.896 ;
    END
  END o[205]
  PIN o[206]
    DIRECTION OUTPUT ;
    USE SIGNAL ;
    PORT
      LAYER M4 ;
        RECT  0 25.968 0.084 25.992 ;
    END
  END o[206]
  PIN o[207]
    DIRECTION OUTPUT ;
    USE SIGNAL ;
    PORT
      LAYER M4 ;
        RECT  0 26.064 0.084 26.088 ;
    END
  END o[207]
  PIN o[208]
    DIRECTION OUTPUT ;
    USE SIGNAL ;
    PORT
      LAYER M4 ;
        RECT  0 26.16 0.084 26.184 ;
    END
  END o[208]
  PIN o[209]
    DIRECTION OUTPUT ;
    USE SIGNAL ;
    PORT
      LAYER M4 ;
        RECT  0 26.256 0.084 26.28 ;
    END
  END o[209]
  PIN o[20]
    DIRECTION OUTPUT ;
    USE SIGNAL ;
    PORT
      LAYER M4 ;
        RECT  0 4.272 0.084 4.296 ;
    END
  END o[20]
  PIN o[210]
    DIRECTION OUTPUT ;
    USE SIGNAL ;
    PORT
      LAYER M4 ;
        RECT  0 26.352 0.084 26.376 ;
    END
  END o[210]
  PIN o[211]
    DIRECTION OUTPUT ;
    USE SIGNAL ;
    PORT
      LAYER M4 ;
        RECT  0 26.448 0.084 26.472 ;
    END
  END o[211]
  PIN o[212]
    DIRECTION OUTPUT ;
    USE SIGNAL ;
    PORT
      LAYER M4 ;
        RECT  0 26.544 0.084 26.568 ;
    END
  END o[212]
  PIN o[213]
    DIRECTION OUTPUT ;
    USE SIGNAL ;
    PORT
      LAYER M4 ;
        RECT  0 26.64 0.084 26.664 ;
    END
  END o[213]
  PIN o[214]
    DIRECTION OUTPUT ;
    USE SIGNAL ;
    PORT
      LAYER M4 ;
        RECT  0 26.736 0.084 26.76 ;
    END
  END o[214]
  PIN o[215]
    DIRECTION OUTPUT ;
    USE SIGNAL ;
    PORT
      LAYER M4 ;
        RECT  0 26.832 0.084 26.856 ;
    END
  END o[215]
  PIN o[216]
    DIRECTION OUTPUT ;
    USE SIGNAL ;
    PORT
      LAYER M4 ;
        RECT  0 26.928 0.084 26.952 ;
    END
  END o[216]
  PIN o[217]
    DIRECTION OUTPUT ;
    USE SIGNAL ;
    PORT
      LAYER M4 ;
        RECT  0 27.024 0.084 27.048 ;
    END
  END o[217]
  PIN o[218]
    DIRECTION OUTPUT ;
    USE SIGNAL ;
    PORT
      LAYER M4 ;
        RECT  0 27.12 0.084 27.144 ;
    END
  END o[218]
  PIN o[219]
    DIRECTION OUTPUT ;
    USE SIGNAL ;
    PORT
      LAYER M4 ;
        RECT  0 27.216 0.084 27.24 ;
    END
  END o[219]
  PIN o[21]
    DIRECTION OUTPUT ;
    USE SIGNAL ;
    PORT
      LAYER M4 ;
        RECT  0 4.368 0.084 4.392 ;
    END
  END o[21]
  PIN o[220]
    DIRECTION OUTPUT ;
    USE SIGNAL ;
    PORT
      LAYER M4 ;
        RECT  0 27.312 0.084 27.336 ;
    END
  END o[220]
  PIN o[221]
    DIRECTION OUTPUT ;
    USE SIGNAL ;
    PORT
      LAYER M4 ;
        RECT  0 27.408 0.084 27.432 ;
    END
  END o[221]
  PIN o[222]
    DIRECTION OUTPUT ;
    USE SIGNAL ;
    PORT
      LAYER M4 ;
        RECT  0 27.504 0.084 27.528 ;
    END
  END o[222]
  PIN o[223]
    DIRECTION OUTPUT ;
    USE SIGNAL ;
    PORT
      LAYER M4 ;
        RECT  0 27.6 0.084 27.624 ;
    END
  END o[223]
  PIN o[224]
    DIRECTION OUTPUT ;
    USE SIGNAL ;
    PORT
      LAYER M4 ;
        RECT  0 27.696 0.084 27.72 ;
    END
  END o[224]
  PIN o[225]
    DIRECTION OUTPUT ;
    USE SIGNAL ;
    PORT
      LAYER M4 ;
        RECT  0 27.792 0.084 27.816 ;
    END
  END o[225]
  PIN o[226]
    DIRECTION OUTPUT ;
    USE SIGNAL ;
    PORT
      LAYER M4 ;
        RECT  0 27.888 0.084 27.912 ;
    END
  END o[226]
  PIN o[227]
    DIRECTION OUTPUT ;
    USE SIGNAL ;
    PORT
      LAYER M4 ;
        RECT  0 27.984 0.084 28.008 ;
    END
  END o[227]
  PIN o[228]
    DIRECTION OUTPUT ;
    USE SIGNAL ;
    PORT
      LAYER M4 ;
        RECT  0 28.08 0.084 28.104 ;
    END
  END o[228]
  PIN o[229]
    DIRECTION OUTPUT ;
    USE SIGNAL ;
    PORT
      LAYER M4 ;
        RECT  0 28.176 0.084 28.2 ;
    END
  END o[229]
  PIN o[22]
    DIRECTION OUTPUT ;
    USE SIGNAL ;
    PORT
      LAYER M4 ;
        RECT  0 4.464 0.084 4.488 ;
    END
  END o[22]
  PIN o[230]
    DIRECTION OUTPUT ;
    USE SIGNAL ;
    PORT
      LAYER M4 ;
        RECT  0 28.272 0.084 28.296 ;
    END
  END o[230]
  PIN o[231]
    DIRECTION OUTPUT ;
    USE SIGNAL ;
    PORT
      LAYER M4 ;
        RECT  0 28.368 0.084 28.392 ;
    END
  END o[231]
  PIN o[232]
    DIRECTION OUTPUT ;
    USE SIGNAL ;
    PORT
      LAYER M4 ;
        RECT  0 28.464 0.084 28.488 ;
    END
  END o[232]
  PIN o[233]
    DIRECTION OUTPUT ;
    USE SIGNAL ;
    PORT
      LAYER M4 ;
        RECT  0 28.56 0.084 28.584 ;
    END
  END o[233]
  PIN o[234]
    DIRECTION OUTPUT ;
    USE SIGNAL ;
    PORT
      LAYER M4 ;
        RECT  0 28.656 0.084 28.68 ;
    END
  END o[234]
  PIN o[235]
    DIRECTION OUTPUT ;
    USE SIGNAL ;
    PORT
      LAYER M4 ;
        RECT  0 28.752 0.084 28.776 ;
    END
  END o[235]
  PIN o[236]
    DIRECTION OUTPUT ;
    USE SIGNAL ;
    PORT
      LAYER M4 ;
        RECT  0 28.848 0.084 28.872 ;
    END
  END o[236]
  PIN o[237]
    DIRECTION OUTPUT ;
    USE SIGNAL ;
    PORT
      LAYER M4 ;
        RECT  0 28.944 0.084 28.968 ;
    END
  END o[237]
  PIN o[238]
    DIRECTION OUTPUT ;
    USE SIGNAL ;
    PORT
      LAYER M4 ;
        RECT  0 29.04 0.084 29.064 ;
    END
  END o[238]
  PIN o[239]
    DIRECTION OUTPUT ;
    USE SIGNAL ;
    PORT
      LAYER M4 ;
        RECT  0 29.136 0.084 29.16 ;
    END
  END o[239]
  PIN o[23]
    DIRECTION OUTPUT ;
    USE SIGNAL ;
    PORT
      LAYER M4 ;
        RECT  0 4.56 0.084 4.584 ;
    END
  END o[23]
  PIN o[240]
    DIRECTION OUTPUT ;
    USE SIGNAL ;
    PORT
      LAYER M4 ;
        RECT  0 29.232 0.084 29.256 ;
    END
  END o[240]
  PIN o[241]
    DIRECTION OUTPUT ;
    USE SIGNAL ;
    PORT
      LAYER M4 ;
        RECT  0 29.328 0.084 29.352 ;
    END
  END o[241]
  PIN o[242]
    DIRECTION OUTPUT ;
    USE SIGNAL ;
    PORT
      LAYER M4 ;
        RECT  0 29.424 0.084 29.448 ;
    END
  END o[242]
  PIN o[243]
    DIRECTION OUTPUT ;
    USE SIGNAL ;
    PORT
      LAYER M4 ;
        RECT  0 29.52 0.084 29.544 ;
    END
  END o[243]
  PIN o[244]
    DIRECTION OUTPUT ;
    USE SIGNAL ;
    PORT
      LAYER M4 ;
        RECT  0 29.616 0.084 29.64 ;
    END
  END o[244]
  PIN o[245]
    DIRECTION OUTPUT ;
    USE SIGNAL ;
    PORT
      LAYER M4 ;
        RECT  0 29.712 0.084 29.736 ;
    END
  END o[245]
  PIN o[246]
    DIRECTION OUTPUT ;
    USE SIGNAL ;
    PORT
      LAYER M4 ;
        RECT  0 29.808 0.084 29.832 ;
    END
  END o[246]
  PIN o[247]
    DIRECTION OUTPUT ;
    USE SIGNAL ;
    PORT
      LAYER M4 ;
        RECT  0 29.904 0.084 29.928 ;
    END
  END o[247]
  PIN o[248]
    DIRECTION OUTPUT ;
    USE SIGNAL ;
    PORT
      LAYER M4 ;
        RECT  0 30 0.084 30.024 ;
    END
  END o[248]
  PIN o[249]
    DIRECTION OUTPUT ;
    USE SIGNAL ;
    PORT
      LAYER M4 ;
        RECT  0 30.096 0.084 30.12 ;
    END
  END o[249]
  PIN o[24]
    DIRECTION OUTPUT ;
    USE SIGNAL ;
    PORT
      LAYER M4 ;
        RECT  0 4.656 0.084 4.68 ;
    END
  END o[24]
  PIN o[250]
    DIRECTION OUTPUT ;
    USE SIGNAL ;
    PORT
      LAYER M4 ;
        RECT  0 30.192 0.084 30.216 ;
    END
  END o[250]
  PIN o[251]
    DIRECTION OUTPUT ;
    USE SIGNAL ;
    PORT
      LAYER M4 ;
        RECT  0 30.288 0.084 30.312 ;
    END
  END o[251]
  PIN o[252]
    DIRECTION OUTPUT ;
    USE SIGNAL ;
    PORT
      LAYER M4 ;
        RECT  0 30.384 0.084 30.408 ;
    END
  END o[252]
  PIN o[253]
    DIRECTION OUTPUT ;
    USE SIGNAL ;
    PORT
      LAYER M4 ;
        RECT  0 30.48 0.084 30.504 ;
    END
  END o[253]
  PIN o[254]
    DIRECTION OUTPUT ;
    USE SIGNAL ;
    PORT
      LAYER M4 ;
        RECT  0 30.576 0.084 30.6 ;
    END
  END o[254]
  PIN o[255]
    DIRECTION OUTPUT ;
    USE SIGNAL ;
    PORT
      LAYER M4 ;
        RECT  0 30.672 0.084 30.696 ;
    END
  END o[255]
  PIN o[256]
    DIRECTION OUTPUT ;
    USE SIGNAL ;
    PORT
      LAYER M4 ;
        RECT  0 11.568 0.084 11.592 ;
    END
  END o[256]
  PIN o[257]
    DIRECTION OUTPUT ;
    USE SIGNAL ;
    PORT
      LAYER M4 ;
        RECT  0 11.664 0.084 11.688 ;
    END
  END o[257]
  PIN o[258]
    DIRECTION OUTPUT ;
    USE SIGNAL ;
    PORT
      LAYER M4 ;
        RECT  0 11.76 0.084 11.784 ;
    END
  END o[258]
  PIN o[259]
    DIRECTION OUTPUT ;
    USE SIGNAL ;
    PORT
      LAYER M4 ;
        RECT  0 11.856 0.084 11.88 ;
    END
  END o[259]
  PIN o[25]
    DIRECTION OUTPUT ;
    USE SIGNAL ;
    PORT
      LAYER M4 ;
        RECT  0 4.752 0.084 4.776 ;
    END
  END o[25]
  PIN o[260]
    DIRECTION OUTPUT ;
    USE SIGNAL ;
    PORT
      LAYER M4 ;
        RECT  0 11.952 0.084 11.976 ;
    END
  END o[260]
  PIN o[261]
    DIRECTION OUTPUT ;
    USE SIGNAL ;
    PORT
      LAYER M4 ;
        RECT  0 12.048 0.084 12.072 ;
    END
  END o[261]
  PIN o[262]
    DIRECTION OUTPUT ;
    USE SIGNAL ;
    PORT
      LAYER M4 ;
        RECT  0 12.144 0.084 12.168 ;
    END
  END o[262]
  PIN o[263]
    DIRECTION OUTPUT ;
    USE SIGNAL ;
    PORT
      LAYER M4 ;
        RECT  0 12.24 0.084 12.264 ;
    END
  END o[263]
  PIN o[264]
    DIRECTION OUTPUT ;
    USE SIGNAL ;
    PORT
      LAYER M4 ;
        RECT  0 12.336 0.084 12.36 ;
    END
  END o[264]
  PIN o[265]
    DIRECTION OUTPUT ;
    USE SIGNAL ;
    PORT
      LAYER M4 ;
        RECT  0 12.432 0.084 12.456 ;
    END
  END o[265]
  PIN o[266]
    DIRECTION OUTPUT ;
    USE SIGNAL ;
    PORT
      LAYER M4 ;
        RECT  0 12.528 0.084 12.552 ;
    END
  END o[266]
  PIN o[267]
    DIRECTION OUTPUT ;
    USE SIGNAL ;
    PORT
      LAYER M4 ;
        RECT  0 12.624 0.084 12.648 ;
    END
  END o[267]
  PIN o[268]
    DIRECTION OUTPUT ;
    USE SIGNAL ;
    PORT
      LAYER M4 ;
        RECT  0 12.72 0.084 12.744 ;
    END
  END o[268]
  PIN o[269]
    DIRECTION OUTPUT ;
    USE SIGNAL ;
    PORT
      LAYER M4 ;
        RECT  0 12.816 0.084 12.84 ;
    END
  END o[269]
  PIN o[26]
    DIRECTION OUTPUT ;
    USE SIGNAL ;
    PORT
      LAYER M4 ;
        RECT  0 4.848 0.084 4.872 ;
    END
  END o[26]
  PIN o[270]
    DIRECTION OUTPUT ;
    USE SIGNAL ;
    PORT
      LAYER M4 ;
        RECT  0 12.912 0.084 12.936 ;
    END
  END o[270]
  PIN o[271]
    DIRECTION OUTPUT ;
    USE SIGNAL ;
    PORT
      LAYER M4 ;
        RECT  0 13.008 0.084 13.032 ;
    END
  END o[271]
  PIN o[272]
    DIRECTION OUTPUT ;
    USE SIGNAL ;
    PORT
      LAYER M4 ;
        RECT  0 13.104 0.084 13.128 ;
    END
  END o[272]
  PIN o[273]
    DIRECTION OUTPUT ;
    USE SIGNAL ;
    PORT
      LAYER M4 ;
        RECT  0 13.2 0.084 13.224 ;
    END
  END o[273]
  PIN o[274]
    DIRECTION OUTPUT ;
    USE SIGNAL ;
    PORT
      LAYER M4 ;
        RECT  0 13.296 0.084 13.32 ;
    END
  END o[274]
  PIN o[275]
    DIRECTION OUTPUT ;
    USE SIGNAL ;
    PORT
      LAYER M4 ;
        RECT  0 13.392 0.084 13.416 ;
    END
  END o[275]
  PIN o[276]
    DIRECTION OUTPUT ;
    USE SIGNAL ;
    PORT
      LAYER M4 ;
        RECT  0 13.488 0.084 13.512 ;
    END
  END o[276]
  PIN o[277]
    DIRECTION OUTPUT ;
    USE SIGNAL ;
    PORT
      LAYER M4 ;
        RECT  0 13.584 0.084 13.608 ;
    END
  END o[277]
  PIN o[278]
    DIRECTION OUTPUT ;
    USE SIGNAL ;
    PORT
      LAYER M4 ;
        RECT  0 13.68 0.084 13.704 ;
    END
  END o[278]
  PIN o[279]
    DIRECTION OUTPUT ;
    USE SIGNAL ;
    PORT
      LAYER M4 ;
        RECT  0 13.776 0.084 13.8 ;
    END
  END o[279]
  PIN o[27]
    DIRECTION OUTPUT ;
    USE SIGNAL ;
    PORT
      LAYER M4 ;
        RECT  0 4.944 0.084 4.968 ;
    END
  END o[27]
  PIN o[280]
    DIRECTION OUTPUT ;
    USE SIGNAL ;
    PORT
      LAYER M4 ;
        RECT  0 13.872 0.084 13.896 ;
    END
  END o[280]
  PIN o[281]
    DIRECTION OUTPUT ;
    USE SIGNAL ;
    PORT
      LAYER M4 ;
        RECT  0 13.968 0.084 13.992 ;
    END
  END o[281]
  PIN o[282]
    DIRECTION OUTPUT ;
    USE SIGNAL ;
    PORT
      LAYER M4 ;
        RECT  0 14.064 0.084 14.088 ;
    END
  END o[282]
  PIN o[283]
    DIRECTION OUTPUT ;
    USE SIGNAL ;
    PORT
      LAYER M4 ;
        RECT  0 14.16 0.084 14.184 ;
    END
  END o[283]
  PIN o[284]
    DIRECTION OUTPUT ;
    USE SIGNAL ;
    PORT
      LAYER M4 ;
        RECT  0 14.256 0.084 14.28 ;
    END
  END o[284]
  PIN o[285]
    DIRECTION OUTPUT ;
    USE SIGNAL ;
    PORT
      LAYER M4 ;
        RECT  0 14.352 0.084 14.376 ;
    END
  END o[285]
  PIN o[286]
    DIRECTION OUTPUT ;
    USE SIGNAL ;
    PORT
      LAYER M4 ;
        RECT  0 14.448 0.084 14.472 ;
    END
  END o[286]
  PIN o[287]
    DIRECTION OUTPUT ;
    USE SIGNAL ;
    PORT
      LAYER M4 ;
        RECT  0 14.544 0.084 14.568 ;
    END
  END o[287]
  PIN o[288]
    DIRECTION OUTPUT ;
    USE SIGNAL ;
    PORT
      LAYER M4 ;
        RECT  0 10.032 0.084 10.056 ;
    END
  END o[288]
  PIN o[289]
    DIRECTION OUTPUT ;
    USE SIGNAL ;
    PORT
      LAYER M4 ;
        RECT  0 10.128 0.084 10.152 ;
    END
  END o[289]
  PIN o[28]
    DIRECTION OUTPUT ;
    USE SIGNAL ;
    PORT
      LAYER M4 ;
        RECT  0 5.04 0.084 5.064 ;
    END
  END o[28]
  PIN o[290]
    DIRECTION OUTPUT ;
    USE SIGNAL ;
    PORT
      LAYER M4 ;
        RECT  0 10.224 0.084 10.248 ;
    END
  END o[290]
  PIN o[291]
    DIRECTION OUTPUT ;
    USE SIGNAL ;
    PORT
      LAYER M4 ;
        RECT  0 10.32 0.084 10.344 ;
    END
  END o[291]
  PIN o[292]
    DIRECTION OUTPUT ;
    USE SIGNAL ;
    PORT
      LAYER M4 ;
        RECT  0 10.416 0.084 10.44 ;
    END
  END o[292]
  PIN o[293]
    DIRECTION OUTPUT ;
    USE SIGNAL ;
    PORT
      LAYER M4 ;
        RECT  0 10.512 0.084 10.536 ;
    END
  END o[293]
  PIN o[294]
    DIRECTION OUTPUT ;
    USE SIGNAL ;
    PORT
      LAYER M4 ;
        RECT  0 10.608 0.084 10.632 ;
    END
  END o[294]
  PIN o[295]
    DIRECTION OUTPUT ;
    USE SIGNAL ;
    PORT
      LAYER M4 ;
        RECT  0 10.704 0.084 10.728 ;
    END
  END o[295]
  PIN o[296]
    DIRECTION OUTPUT ;
    USE SIGNAL ;
    PORT
      LAYER M4 ;
        RECT  0 10.8 0.084 10.824 ;
    END
  END o[296]
  PIN o[297]
    DIRECTION OUTPUT ;
    USE SIGNAL ;
    PORT
      LAYER M4 ;
        RECT  0 10.896 0.084 10.92 ;
    END
  END o[297]
  PIN o[298]
    DIRECTION OUTPUT ;
    USE SIGNAL ;
    PORT
      LAYER M4 ;
        RECT  0 10.992 0.084 11.016 ;
    END
  END o[298]
  PIN o[299]
    DIRECTION OUTPUT ;
    USE SIGNAL ;
    PORT
      LAYER M4 ;
        RECT  0 11.088 0.084 11.112 ;
    END
  END o[299]
  PIN o[29]
    DIRECTION OUTPUT ;
    USE SIGNAL ;
    PORT
      LAYER M4 ;
        RECT  0 5.136 0.084 5.16 ;
    END
  END o[29]
  PIN o[2]
    DIRECTION OUTPUT ;
    USE SIGNAL ;
    PORT
      LAYER M4 ;
        RECT  0 2.544 0.084 2.568 ;
    END
  END o[2]
  PIN o[300]
    DIRECTION OUTPUT ;
    USE SIGNAL ;
    PORT
      LAYER M4 ;
        RECT  0 11.184 0.084 11.208 ;
    END
  END o[300]
  PIN o[301]
    DIRECTION OUTPUT ;
    USE SIGNAL ;
    PORT
      LAYER M4 ;
        RECT  0 11.28 0.084 11.304 ;
    END
  END o[301]
  PIN o[302]
    DIRECTION OUTPUT ;
    USE SIGNAL ;
    PORT
      LAYER M4 ;
        RECT  0 11.376 0.084 11.4 ;
    END
  END o[302]
  PIN o[303]
    DIRECTION OUTPUT ;
    USE SIGNAL ;
    PORT
      LAYER M4 ;
        RECT  0 11.472 0.084 11.496 ;
    END
  END o[303]
  PIN o[30]
    DIRECTION OUTPUT ;
    USE SIGNAL ;
    PORT
      LAYER M4 ;
        RECT  0 5.232 0.084 5.256 ;
    END
  END o[30]
  PIN o[31]
    DIRECTION OUTPUT ;
    USE SIGNAL ;
    PORT
      LAYER M4 ;
        RECT  0 5.328 0.084 5.352 ;
    END
  END o[31]
  PIN o[32]
    DIRECTION OUTPUT ;
    USE SIGNAL ;
    PORT
      LAYER M4 ;
        RECT  0 18.48 0.084 18.504 ;
    END
  END o[32]
  PIN o[33]
    DIRECTION OUTPUT ;
    USE SIGNAL ;
    PORT
      LAYER M4 ;
        RECT  0 18.576 0.084 18.6 ;
    END
  END o[33]
  PIN o[34]
    DIRECTION OUTPUT ;
    USE SIGNAL ;
    PORT
      LAYER M4 ;
        RECT  0 18.672 0.084 18.696 ;
    END
  END o[34]
  PIN o[35]
    DIRECTION OUTPUT ;
    USE SIGNAL ;
    PORT
      LAYER M4 ;
        RECT  0 18.768 0.084 18.792 ;
    END
  END o[35]
  PIN o[36]
    DIRECTION OUTPUT ;
    USE SIGNAL ;
    PORT
      LAYER M4 ;
        RECT  0 18.864 0.084 18.888 ;
    END
  END o[36]
  PIN o[37]
    DIRECTION OUTPUT ;
    USE SIGNAL ;
    PORT
      LAYER M4 ;
        RECT  0 18.96 0.084 18.984 ;
    END
  END o[37]
  PIN o[38]
    DIRECTION OUTPUT ;
    USE SIGNAL ;
    PORT
      LAYER M4 ;
        RECT  0 19.056 0.084 19.08 ;
    END
  END o[38]
  PIN o[39]
    DIRECTION OUTPUT ;
    USE SIGNAL ;
    PORT
      LAYER M4 ;
        RECT  0 19.152 0.084 19.176 ;
    END
  END o[39]
  PIN o[3]
    DIRECTION OUTPUT ;
    USE SIGNAL ;
    PORT
      LAYER M4 ;
        RECT  0 2.64 0.084 2.664 ;
    END
  END o[3]
  PIN o[40]
    DIRECTION OUTPUT ;
    USE SIGNAL ;
    PORT
      LAYER M4 ;
        RECT  0 19.248 0.084 19.272 ;
    END
  END o[40]
  PIN o[41]
    DIRECTION OUTPUT ;
    USE SIGNAL ;
    PORT
      LAYER M4 ;
        RECT  0 19.344 0.084 19.368 ;
    END
  END o[41]
  PIN o[42]
    DIRECTION OUTPUT ;
    USE SIGNAL ;
    PORT
      LAYER M4 ;
        RECT  0 19.44 0.084 19.464 ;
    END
  END o[42]
  PIN o[43]
    DIRECTION OUTPUT ;
    USE SIGNAL ;
    PORT
      LAYER M4 ;
        RECT  0 19.536 0.084 19.56 ;
    END
  END o[43]
  PIN o[44]
    DIRECTION OUTPUT ;
    USE SIGNAL ;
    PORT
      LAYER M4 ;
        RECT  0 19.632 0.084 19.656 ;
    END
  END o[44]
  PIN o[45]
    DIRECTION OUTPUT ;
    USE SIGNAL ;
    PORT
      LAYER M4 ;
        RECT  0 19.728 0.084 19.752 ;
    END
  END o[45]
  PIN o[46]
    DIRECTION OUTPUT ;
    USE SIGNAL ;
    PORT
      LAYER M4 ;
        RECT  0 19.824 0.084 19.848 ;
    END
  END o[46]
  PIN o[47]
    DIRECTION OUTPUT ;
    USE SIGNAL ;
    PORT
      LAYER M4 ;
        RECT  0 19.92 0.084 19.944 ;
    END
  END o[47]
  PIN o[48]
    DIRECTION OUTPUT ;
    USE SIGNAL ;
    PORT
      LAYER M4 ;
        RECT  0 20.016 0.084 20.04 ;
    END
  END o[48]
  PIN o[49]
    DIRECTION OUTPUT ;
    USE SIGNAL ;
    PORT
      LAYER M4 ;
        RECT  0 20.112 0.084 20.136 ;
    END
  END o[49]
  PIN o[4]
    DIRECTION OUTPUT ;
    USE SIGNAL ;
    PORT
      LAYER M4 ;
        RECT  0 2.736 0.084 2.76 ;
    END
  END o[4]
  PIN o[50]
    DIRECTION OUTPUT ;
    USE SIGNAL ;
    PORT
      LAYER M4 ;
        RECT  0 20.208 0.084 20.232 ;
    END
  END o[50]
  PIN o[51]
    DIRECTION OUTPUT ;
    USE SIGNAL ;
    PORT
      LAYER M4 ;
        RECT  0 20.304 0.084 20.328 ;
    END
  END o[51]
  PIN o[52]
    DIRECTION OUTPUT ;
    USE SIGNAL ;
    PORT
      LAYER M4 ;
        RECT  0 20.4 0.084 20.424 ;
    END
  END o[52]
  PIN o[53]
    DIRECTION OUTPUT ;
    USE SIGNAL ;
    PORT
      LAYER M4 ;
        RECT  0 20.496 0.084 20.52 ;
    END
  END o[53]
  PIN o[54]
    DIRECTION OUTPUT ;
    USE SIGNAL ;
    PORT
      LAYER M4 ;
        RECT  0 20.592 0.084 20.616 ;
    END
  END o[54]
  PIN o[55]
    DIRECTION OUTPUT ;
    USE SIGNAL ;
    PORT
      LAYER M4 ;
        RECT  0 20.688 0.084 20.712 ;
    END
  END o[55]
  PIN o[56]
    DIRECTION OUTPUT ;
    USE SIGNAL ;
    PORT
      LAYER M4 ;
        RECT  0 20.784 0.084 20.808 ;
    END
  END o[56]
  PIN o[57]
    DIRECTION OUTPUT ;
    USE SIGNAL ;
    PORT
      LAYER M4 ;
        RECT  0 20.88 0.084 20.904 ;
    END
  END o[57]
  PIN o[58]
    DIRECTION OUTPUT ;
    USE SIGNAL ;
    PORT
      LAYER M4 ;
        RECT  0 20.976 0.084 21 ;
    END
  END o[58]
  PIN o[59]
    DIRECTION OUTPUT ;
    USE SIGNAL ;
    PORT
      LAYER M4 ;
        RECT  0 21.072 0.084 21.096 ;
    END
  END o[59]
  PIN o[5]
    DIRECTION OUTPUT ;
    USE SIGNAL ;
    PORT
      LAYER M4 ;
        RECT  0 2.832 0.084 2.856 ;
    END
  END o[5]
  PIN o[60]
    DIRECTION OUTPUT ;
    USE SIGNAL ;
    PORT
      LAYER M4 ;
        RECT  0 21.168 0.084 21.192 ;
    END
  END o[60]
  PIN o[61]
    DIRECTION OUTPUT ;
    USE SIGNAL ;
    PORT
      LAYER M4 ;
        RECT  0 21.264 0.084 21.288 ;
    END
  END o[61]
  PIN o[62]
    DIRECTION OUTPUT ;
    USE SIGNAL ;
    PORT
      LAYER M4 ;
        RECT  0 21.36 0.084 21.384 ;
    END
  END o[62]
  PIN o[63]
    DIRECTION OUTPUT ;
    USE SIGNAL ;
    PORT
      LAYER M4 ;
        RECT  0 21.456 0.084 21.48 ;
    END
  END o[63]
  PIN o[64]
    DIRECTION OUTPUT ;
    USE SIGNAL ;
    PORT
      LAYER M4 ;
        RECT  0 30.768 0.084 30.792 ;
    END
  END o[64]
  PIN o[65]
    DIRECTION OUTPUT ;
    USE SIGNAL ;
    PORT
      LAYER M4 ;
        RECT  0 30.864 0.084 30.888 ;
    END
  END o[65]
  PIN o[66]
    DIRECTION OUTPUT ;
    USE SIGNAL ;
    PORT
      LAYER M4 ;
        RECT  0 30.96 0.084 30.984 ;
    END
  END o[66]
  PIN o[67]
    DIRECTION OUTPUT ;
    USE SIGNAL ;
    PORT
      LAYER M4 ;
        RECT  0 31.056 0.084 31.08 ;
    END
  END o[67]
  PIN o[68]
    DIRECTION OUTPUT ;
    USE SIGNAL ;
    PORT
      LAYER M4 ;
        RECT  0 31.152 0.084 31.176 ;
    END
  END o[68]
  PIN o[69]
    DIRECTION OUTPUT ;
    USE SIGNAL ;
    PORT
      LAYER M4 ;
        RECT  0 31.248 0.084 31.272 ;
    END
  END o[69]
  PIN o[6]
    DIRECTION OUTPUT ;
    USE SIGNAL ;
    PORT
      LAYER M4 ;
        RECT  0 2.928 0.084 2.952 ;
    END
  END o[6]
  PIN o[70]
    DIRECTION OUTPUT ;
    USE SIGNAL ;
    PORT
      LAYER M4 ;
        RECT  0 31.344 0.084 31.368 ;
    END
  END o[70]
  PIN o[71]
    DIRECTION OUTPUT ;
    USE SIGNAL ;
    PORT
      LAYER M4 ;
        RECT  0 31.44 0.084 31.464 ;
    END
  END o[71]
  PIN o[72]
    DIRECTION OUTPUT ;
    USE SIGNAL ;
    PORT
      LAYER M4 ;
        RECT  0 31.536 0.084 31.56 ;
    END
  END o[72]
  PIN o[73]
    DIRECTION OUTPUT ;
    USE SIGNAL ;
    PORT
      LAYER M4 ;
        RECT  0 31.632 0.084 31.656 ;
    END
  END o[73]
  PIN o[74]
    DIRECTION OUTPUT ;
    USE SIGNAL ;
    PORT
      LAYER M4 ;
        RECT  0 31.728 0.084 31.752 ;
    END
  END o[74]
  PIN o[75]
    DIRECTION OUTPUT ;
    USE SIGNAL ;
    PORT
      LAYER M4 ;
        RECT  0 31.824 0.084 31.848 ;
    END
  END o[75]
  PIN o[76]
    DIRECTION OUTPUT ;
    USE SIGNAL ;
    PORT
      LAYER M4 ;
        RECT  0 31.92 0.084 31.944 ;
    END
  END o[76]
  PIN o[77]
    DIRECTION OUTPUT ;
    USE SIGNAL ;
    PORT
      LAYER M4 ;
        RECT  0 32.016 0.084 32.04 ;
    END
  END o[77]
  PIN o[78]
    DIRECTION OUTPUT ;
    USE SIGNAL ;
    PORT
      LAYER M4 ;
        RECT  0 32.112 0.084 32.136 ;
    END
  END o[78]
  PIN o[79]
    DIRECTION OUTPUT ;
    USE SIGNAL ;
    PORT
      LAYER M4 ;
        RECT  0 32.208 0.084 32.232 ;
    END
  END o[79]
  PIN o[7]
    DIRECTION OUTPUT ;
    USE SIGNAL ;
    PORT
      LAYER M4 ;
        RECT  0 3.024 0.084 3.048 ;
    END
  END o[7]
  PIN o[80]
    DIRECTION OUTPUT ;
    USE SIGNAL ;
    PORT
      LAYER M4 ;
        RECT  0 32.304 0.084 32.328 ;
    END
  END o[80]
  PIN o[81]
    DIRECTION OUTPUT ;
    USE SIGNAL ;
    PORT
      LAYER M4 ;
        RECT  0 32.4 0.084 32.424 ;
    END
  END o[81]
  PIN o[82]
    DIRECTION OUTPUT ;
    USE SIGNAL ;
    PORT
      LAYER M4 ;
        RECT  0 32.496 0.084 32.52 ;
    END
  END o[82]
  PIN o[83]
    DIRECTION OUTPUT ;
    USE SIGNAL ;
    PORT
      LAYER M4 ;
        RECT  0 32.592 0.084 32.616 ;
    END
  END o[83]
  PIN o[84]
    DIRECTION OUTPUT ;
    USE SIGNAL ;
    PORT
      LAYER M4 ;
        RECT  0 32.688 0.084 32.712 ;
    END
  END o[84]
  PIN o[85]
    DIRECTION OUTPUT ;
    USE SIGNAL ;
    PORT
      LAYER M4 ;
        RECT  0 32.784 0.084 32.808 ;
    END
  END o[85]
  PIN o[86]
    DIRECTION OUTPUT ;
    USE SIGNAL ;
    PORT
      LAYER M4 ;
        RECT  0 32.88 0.084 32.904 ;
    END
  END o[86]
  PIN o[87]
    DIRECTION OUTPUT ;
    USE SIGNAL ;
    PORT
      LAYER M4 ;
        RECT  0 32.976 0.084 33 ;
    END
  END o[87]
  PIN o[88]
    DIRECTION OUTPUT ;
    USE SIGNAL ;
    PORT
      LAYER M4 ;
        RECT  0 33.072 0.084 33.096 ;
    END
  END o[88]
  PIN o[89]
    DIRECTION OUTPUT ;
    USE SIGNAL ;
    PORT
      LAYER M4 ;
        RECT  0 33.168 0.084 33.192 ;
    END
  END o[89]
  PIN o[8]
    DIRECTION OUTPUT ;
    USE SIGNAL ;
    PORT
      LAYER M4 ;
        RECT  0 3.12 0.084 3.144 ;
    END
  END o[8]
  PIN o[90]
    DIRECTION OUTPUT ;
    USE SIGNAL ;
    PORT
      LAYER M4 ;
        RECT  0 33.264 0.084 33.288 ;
    END
  END o[90]
  PIN o[91]
    DIRECTION OUTPUT ;
    USE SIGNAL ;
    PORT
      LAYER M4 ;
        RECT  0 33.36 0.084 33.384 ;
    END
  END o[91]
  PIN o[92]
    DIRECTION OUTPUT ;
    USE SIGNAL ;
    PORT
      LAYER M4 ;
        RECT  0 33.456 0.084 33.48 ;
    END
  END o[92]
  PIN o[93]
    DIRECTION OUTPUT ;
    USE SIGNAL ;
    PORT
      LAYER M4 ;
        RECT  0 33.552 0.084 33.576 ;
    END
  END o[93]
  PIN o[94]
    DIRECTION OUTPUT ;
    USE SIGNAL ;
    PORT
      LAYER M4 ;
        RECT  0 33.648 0.084 33.672 ;
    END
  END o[94]
  PIN o[95]
    DIRECTION OUTPUT ;
    USE SIGNAL ;
    PORT
      LAYER M4 ;
        RECT  0 33.744 0.084 33.768 ;
    END
  END o[95]
  PIN o[96]
    DIRECTION OUTPUT ;
    USE SIGNAL ;
    PORT
      LAYER M4 ;
        RECT  0 15.408 0.084 15.432 ;
    END
  END o[96]
  PIN o[97]
    DIRECTION OUTPUT ;
    USE SIGNAL ;
    PORT
      LAYER M4 ;
        RECT  0 15.504 0.084 15.528 ;
    END
  END o[97]
  PIN o[98]
    DIRECTION OUTPUT ;
    USE SIGNAL ;
    PORT
      LAYER M4 ;
        RECT  0 15.6 0.084 15.624 ;
    END
  END o[98]
  PIN o[99]
    DIRECTION OUTPUT ;
    USE SIGNAL ;
    PORT
      LAYER M4 ;
        RECT  0 15.696 0.084 15.72 ;
    END
  END o[99]
  PIN o[9]
    DIRECTION OUTPUT ;
    USE SIGNAL ;
    PORT
      LAYER M4 ;
        RECT  0 3.216 0.084 3.24 ;
    END
  END o[9]
  PIN rs
    DIRECTION INPUT ;
    USE SIGNAL ;
    PORT
      LAYER M5 ;
        RECT  12.912 0 12.936 0.084 ;
    END
  END rs
  PIN VDD
    DIRECTION INOUT ;
    USE POWER ;
    PORT
      LAYER M5 ;
        RECT  18.792 2.151 18.912 32.409 ;
        RECT  16.092 2.151 16.212 32.409 ;
        RECT  13.392 2.151 13.512 32.409 ;
        RECT  10.692 2.151 10.812 32.409 ;
        RECT  7.992 2.151 8.112 32.409 ;
        RECT  5.292 2.151 5.412 32.409 ;
        RECT  2.592 2.151 2.712 32.409 ;
    END
  END VDD
  PIN VSS
    DIRECTION INOUT ;
    USE GROUND ;
    PORT
      LAYER M5 ;
        RECT  18.6 2.137 18.72 32.423 ;
        RECT  15.9 2.137 16.02 32.423 ;
        RECT  13.2 2.137 13.32 32.423 ;
        RECT  10.5 2.137 10.62 32.423 ;
        RECT  7.8 2.137 7.92 32.423 ;
        RECT  5.1 2.137 5.22 32.423 ;
        RECT  2.4 2.137 2.52 32.423 ;
    END
  END VSS
  # OT_OBS_CLOSED layer=M5 d_um=1.536 added=82
  OBS
    LAYER RVTN ;
     RECT  2.16 2.16 19.44 2.295 ;
     RECT  2.16 2.565 19.44 2.835 ;
     RECT  2.16 3.105 19.44 3.375 ;
     RECT  2.16 3.645 19.44 3.915 ;
     RECT  2.16 4.185 19.44 4.455 ;
     RECT  2.16 4.725 19.44 4.995 ;
     RECT  2.16 5.265 19.44 5.535 ;
     RECT  2.16 5.805 19.44 6.075 ;
     RECT  2.16 6.345 19.44 6.615 ;
     RECT  2.16 6.885 19.44 7.155 ;
     RECT  2.16 7.425 19.44 7.695 ;
     RECT  2.16 7.965 19.44 8.235 ;
     RECT  2.16 8.505 19.44 8.775 ;
     RECT  2.16 9.045 19.44 9.315 ;
     RECT  2.16 9.585 19.44 9.855 ;
     RECT  2.16 10.125 19.44 10.395 ;
     RECT  2.16 10.665 19.44 10.935 ;
     RECT  2.16 11.205 19.44 11.475 ;
     RECT  2.16 11.745 19.44 12.015 ;
     RECT  2.16 12.285 19.44 12.555 ;
     RECT  2.16 12.825 19.44 13.095 ;
     RECT  2.16 13.365 19.44 13.635 ;
     RECT  2.16 13.905 19.44 14.175 ;
     RECT  2.16 14.445 19.44 14.715 ;
     RECT  2.16 14.985 19.44 15.255 ;
     RECT  2.16 15.525 19.44 15.795 ;
     RECT  2.16 16.065 19.44 16.335 ;
     RECT  2.16 16.605 19.44 16.875 ;
     RECT  2.16 17.145 19.44 17.415 ;
     RECT  2.16 17.685 19.44 17.955 ;
     RECT  2.16 18.225 19.44 18.495 ;
     RECT  2.16 18.765 19.44 19.035 ;
     RECT  2.16 19.305 19.44 19.575 ;
     RECT  2.16 19.845 19.44 20.115 ;
     RECT  2.16 20.385 19.44 20.655 ;
     RECT  2.16 20.925 19.44 21.195 ;
     RECT  2.16 21.465 19.44 21.735 ;
     RECT  2.16 22.005 19.44 22.275 ;
     RECT  2.16 22.545 19.44 22.815 ;
     RECT  2.16 23.085 19.44 23.355 ;
     RECT  2.16 23.625 19.44 23.895 ;
     RECT  2.16 24.165 19.44 24.435 ;
     RECT  2.16 24.705 19.44 24.975 ;
     RECT  2.16 25.245 19.44 25.515 ;
     RECT  2.16 25.785 19.44 26.055 ;
     RECT  2.16 26.325 19.44 26.595 ;
     RECT  2.16 26.865 19.44 27.135 ;
     RECT  2.16 27.405 19.44 27.675 ;
     RECT  2.16 27.945 19.44 28.215 ;
     RECT  2.16 28.485 19.44 28.755 ;
     RECT  2.16 29.025 19.44 29.295 ;
     RECT  2.16 29.565 19.44 29.835 ;
     RECT  2.16 30.105 19.44 30.375 ;
     RECT  2.16 30.645 19.44 30.915 ;
     RECT  2.16 31.185 19.44 31.455 ;
     RECT  2.16 31.725 19.44 31.995 ;
     RECT  2.16 32.265 19.44 32.4 ;
    LAYER RVTP ;
     RECT  2.16 2.295 19.44 2.565 ;
     RECT  2.16 2.835 19.44 3.105 ;
     RECT  2.16 3.375 19.44 3.645 ;
     RECT  2.16 3.915 19.44 4.185 ;
     RECT  2.16 4.455 19.44 4.725 ;
     RECT  2.16 4.995 19.44 5.265 ;
     RECT  2.16 5.535 19.44 5.805 ;
     RECT  2.16 6.075 19.44 6.345 ;
     RECT  2.16 6.615 19.44 6.885 ;
     RECT  2.16 7.155 19.44 7.425 ;
     RECT  2.16 7.695 19.44 7.965 ;
     RECT  2.16 8.235 19.44 8.505 ;
     RECT  2.16 8.775 19.44 9.045 ;
     RECT  2.16 9.315 19.44 9.585 ;
     RECT  2.16 9.855 19.44 10.125 ;
     RECT  2.16 10.395 19.44 10.665 ;
     RECT  2.16 10.935 19.44 11.205 ;
     RECT  2.16 11.475 19.44 11.745 ;
     RECT  2.16 12.015 19.44 12.285 ;
     RECT  2.16 12.555 19.44 12.825 ;
     RECT  2.16 13.095 19.44 13.365 ;
     RECT  2.16 13.635 19.44 13.905 ;
     RECT  2.16 14.175 19.44 14.445 ;
     RECT  2.16 14.715 19.44 14.985 ;
     RECT  2.16 15.255 19.44 15.525 ;
     RECT  2.16 15.795 19.44 16.065 ;
     RECT  2.16 16.335 19.44 16.605 ;
     RECT  2.16 16.875 19.44 17.145 ;
     RECT  2.16 17.415 19.44 17.685 ;
     RECT  2.16 17.955 19.44 18.225 ;
     RECT  2.16 18.495 19.44 18.765 ;
     RECT  2.16 19.035 19.44 19.305 ;
     RECT  2.16 19.575 19.44 19.845 ;
     RECT  2.16 20.115 19.44 20.385 ;
     RECT  2.16 20.655 19.44 20.925 ;
     RECT  2.16 21.195 19.44 21.465 ;
     RECT  2.16 21.735 19.44 22.005 ;
     RECT  2.16 22.275 19.44 22.545 ;
     RECT  2.16 22.815 19.44 23.085 ;
     RECT  2.16 23.355 19.44 23.625 ;
     RECT  2.16 23.895 19.44 24.165 ;
     RECT  2.16 24.435 19.44 24.705 ;
     RECT  2.16 24.975 19.44 25.245 ;
     RECT  2.16 25.515 19.44 25.785 ;
     RECT  2.16 26.055 19.44 26.325 ;
     RECT  2.16 26.595 19.44 26.865 ;
     RECT  2.16 27.135 19.44 27.405 ;
     RECT  2.16 27.675 19.44 27.945 ;
     RECT  2.16 28.215 19.44 28.485 ;
     RECT  2.16 28.755 19.44 29.025 ;
     RECT  2.16 29.295 19.44 29.565 ;
     RECT  2.16 29.835 19.44 30.105 ;
     RECT  2.16 30.375 19.44 30.645 ;
     RECT  2.16 30.915 19.44 31.185 ;
     RECT  2.16 31.455 19.44 31.725 ;
     RECT  2.16 31.995 19.44 32.265 ;
    LAYER M1 ;
     RECT  2.16 2.151 19.44 32.409 ;
    LAYER M2 ;
     RECT  0.031 30.114 0.067 30.132 ;
     RECT  0.031 32.121 0.067 32.139 ;
     RECT  0.067 30.114 0.103 30.672 ;
     RECT  0.067 32.121 0.131 32.292 ;
     RECT  0.103 18.126 0.139 18.144 ;
     RECT  0.103 20.196 0.139 20.214 ;
     RECT  0.103 25.056 0.139 26.352 ;
     RECT  0.103 27.216 0.139 27.864 ;
     RECT  0.131 32.274 0.167 32.292 ;
     RECT  0.103 15.336 0.175 16.164 ;
     RECT  0.103 16.956 0.175 16.974 ;
     RECT  0.139 17.964 0.175 18.144 ;
     RECT  0.139 19.746 0.175 20.214 ;
     RECT  0.139 25.056 0.175 28.404 ;
     RECT  0.103 29.538 0.175 31.014 ;
     RECT  0.103 6.822 0.203 6.912 ;
     RECT  0.175 19.746 0.211 20.754 ;
     RECT  0.103 12.996 0.239 13.824 ;
     RECT  0.103 22.212 0.247 22.23 ;
     RECT  0.103 23.256 0.247 23.886 ;
     RECT  0.239 13.806 0.283 13.824 ;
     RECT  0.319 10.791 0.355 10.809 ;
     RECT  0.355 10.674 0.391 10.809 ;
     RECT  0.391 10.404 0.427 10.809 ;
     RECT  0.427 9.936 0.463 10.809 ;
     RECT  0.239 12.996 0.463 13.014 ;
     RECT  0.283 13.806 0.463 14.544 ;
     RECT  0.175 15.336 0.463 18.144 ;
     RECT  0.463 12.366 0.499 13.014 ;
     RECT  0.247 22.212 0.499 23.886 ;
     RECT  0.103 2.196 0.535 2.214 ;
     RECT  0.499 3.456 0.535 3.474 ;
     RECT  0.203 6.822 0.535 6.84 ;
     RECT  0.463 9.936 0.535 11.304 ;
     RECT  0.499 12.294 0.535 13.014 ;
     RECT  0.211 19.746 0.535 20.844 ;
     RECT  0.499 22.014 0.535 23.886 ;
     RECT  0.535 6.084 1.147 6.84 ;
     RECT  0.175 25.02 1.183 31.014 ;
     RECT  1.147 31.896 1.183 31.914 ;
     RECT  0.535 9.936 1.399 13.014 ;
     RECT  0.535 2.196 2.16 3.474 ;
     RECT  0.103 4.266 2.16 4.284 ;
     RECT  1.147 6.084 2.16 7.452 ;
     RECT  1.399 9.324 2.16 13.014 ;
     RECT  0.463 13.806 2.16 18.144 ;
     RECT  0.535 19.656 2.16 23.886 ;
     RECT  1.183 25.02 2.16 31.914 ;
     RECT  2.16 2.151 2.551 32.409 ;
     RECT  2.551 2.106 3.343 32.409 ;
     RECT  3.343 2.034 3.667 32.409 ;
     RECT  3.667 2.034 3.703 32.454 ;
     RECT  3.703 2.034 4.235 32.49 ;
     RECT  4.235 2.07 6.683 32.49 ;
     RECT  6.683 2.07 6.719 32.454 ;
     RECT  6.719 2.106 7.691 32.454 ;
     RECT  7.691 2.151 7.699 32.454 ;
     RECT  7.699 2.151 13.703 32.49 ;
     RECT  13.703 2.151 16.555 32.409 ;
     RECT  16.555 2.034 17.023 32.409 ;
     RECT  17.023 1.881 19.44 32.409 ;
     RECT  19.44 1.881 19.859 32.328 ;
     RECT  19.859 1.962 19.967 32.328 ;
     RECT  19.967 1.962 20.003 21.456 ;
     RECT  20.003 4.23 20.219 21.456 ;
     RECT  20.219 14.724 20.327 21.456 ;
     RECT  19.967 22.788 20.327 32.328 ;
     RECT  20.219 4.23 20.399 13.968 ;
     RECT  20.327 14.724 20.399 17.784 ;
     RECT  20.327 18.738 20.399 21.456 ;
     RECT  20.399 4.23 20.435 13.086 ;
     RECT  20.399 14.724 20.435 15.246 ;
     RECT  20.399 18.738 20.435 20.106 ;
     RECT  20.399 20.934 20.435 21.456 ;
     RECT  20.327 22.788 20.435 31.176 ;
     RECT  20.435 11.826 20.471 13.086 ;
     RECT  20.399 13.878 20.471 13.968 ;
     RECT  20.435 20.934 20.471 21.258 ;
     RECT  20.435 24.948 20.471 30.132 ;
     RECT  20.003 1.962 20.507 3.402 ;
     RECT  20.435 4.23 20.507 10.998 ;
     RECT  20.471 11.826 20.507 12.546 ;
     RECT  20.471 21.168 20.507 21.258 ;
     RECT  20.471 24.948 20.507 24.966 ;
     RECT  20.471 26.136 20.507 30.132 ;
     RECT  20.327 32.076 20.507 32.328 ;
     RECT  20.507 5.04 20.543 10.998 ;
     RECT  20.471 13.95 20.543 13.968 ;
     RECT  20.399 16.11 20.543 17.784 ;
     RECT  20.435 19.278 20.543 19.836 ;
     RECT  20.507 21.24 20.543 21.258 ;
     RECT  20.435 22.788 20.543 23.922 ;
     RECT  20.507 26.136 20.543 28.584 ;
     RECT  20.507 29.34 20.543 29.358 ;
     RECT  20.435 31.158 20.543 31.176 ;
     RECT  20.507 2.34 20.579 3.402 ;
     RECT  20.543 5.31 20.579 10.224 ;
     RECT  20.435 14.724 20.579 15.048 ;
     RECT  20.543 26.136 20.579 26.892 ;
     RECT  20.543 27.756 20.579 27.774 ;
     RECT  20.543 16.308 20.615 17.478 ;
     RECT  20.579 6.426 21.407 10.224 ;
     RECT  21.407 8.172 21.443 10.224 ;
     RECT  20.579 14.958 21.443 15.048 ;
     RECT  20.579 26.838 21.443 26.856 ;
     RECT  20.579 2.61 21.479 3.402 ;
     RECT  21.407 6.426 21.479 7.146 ;
     RECT  21.443 9.666 21.479 10.224 ;
     RECT  21.443 15.03 21.479 15.048 ;
     RECT  21.479 3.384 21.515 3.402 ;
     RECT  20.579 5.31 21.515 5.328 ;
     RECT  21.479 6.426 21.515 6.84 ;
     RECT  21.443 8.172 21.515 8.874 ;
     RECT  21.479 9.666 21.515 9.954 ;
     RECT  20.615 17.46 21.515 17.478 ;
     RECT  20.543 19.818 21.515 19.836 ;
     RECT  20.543 23.058 21.515 23.076 ;
     RECT  20.543 28.566 21.515 28.584 ;
     RECT  20.507 32.076 21.515 32.094 ;
     RECT  21.487 1.422 21.587 1.44 ;
     RECT  20.507 4.23 21.587 4.248 ;
    LAYER M3 ;
     RECT  19.368 0.715 19.386 0.811 ;
     RECT  19.368 0.811 19.926 0.907 ;
     RECT  19.368 0.907 20.43 1.003 ;
     RECT  21.492 1.387 21.51 1.417 ;
     RECT  19.368 1.003 20.502 1.483 ;
     RECT  19.188 1.483 20.502 1.867 ;
     RECT  17.964 1.921 17.982 1.957 ;
     RECT  17.964 1.957 18.234 1.993 ;
     RECT  19.188 1.867 20.538 1.993 ;
     RECT  17.028 1.876 17.046 2.029 ;
     RECT  4.212 2.029 4.23 2.065 ;
     RECT  3.348 2.029 3.366 2.101 ;
     RECT  4.212 2.065 4.626 2.101 ;
     RECT  16.56 2.029 17.046 2.101 ;
     RECT  17.964 1.993 20.538 2.101 ;
     RECT  2.556 2.101 2.574 2.143 ;
     RECT  3.348 2.101 4.626 2.143 ;
     RECT  5.616 2.065 5.706 2.143 ;
     RECT  7.668 2.101 7.686 2.143 ;
     RECT  12.996 1.723 13.014 2.143 ;
     RECT  16.56 2.101 20.538 2.143 ;
     RECT  2.415 2.143 2.574 2.191 ;
     RECT  3.348 2.143 5.706 2.191 ;
     RECT  6.696 2.065 6.714 2.191 ;
     RECT  2.415 2.191 5.706 2.299 ;
     RECT  6.516 2.191 6.714 2.299 ;
     RECT  7.668 2.143 7.905 2.299 ;
     RECT  2.415 2.299 6.714 2.335 ;
     RECT  10.515 2.143 10.605 2.335 ;
     RECT  11.844 2.263 11.862 2.335 ;
     RECT  12.996 2.143 13.305 2.335 ;
     RECT  15.915 2.143 20.538 2.335 ;
     RECT  2.304 2.335 6.714 2.371 ;
     RECT  7.596 2.299 7.905 2.371 ;
     RECT  9.216 2.191 9.234 2.371 ;
     RECT  10.515 2.335 10.926 2.371 ;
     RECT  15.915 2.335 20.574 2.381 ;
     RECT  2.304 2.371 7.905 2.413 ;
     RECT  11.844 2.335 13.305 2.413 ;
     RECT  0.108 2.191 0.126 2.477 ;
     RECT  11.844 2.413 13.497 2.539 ;
     RECT  21.492 1.417 21.582 2.539 ;
     RECT  10.26 2.371 10.926 2.641 ;
     RECT  11.844 2.539 13.698 2.641 ;
     RECT  15.915 2.381 20.538 2.669 ;
     RECT  2.304 2.413 8.097 2.731 ;
     RECT  9.108 2.371 9.234 2.731 ;
     RECT  10.26 2.641 13.698 2.731 ;
     RECT  10.26 2.731 14.094 2.779 ;
     RECT  14.868 2.569 14.958 2.779 ;
     RECT  0.324 2.641 0.558 2.861 ;
     RECT  10.26 2.779 14.958 2.875 ;
     RECT  15.915 2.669 20.502 2.875 ;
     RECT  10.26 2.875 20.502 3.019 ;
     RECT  21.456 2.539 21.582 3.067 ;
     RECT  2.304 2.731 9.234 3.145 ;
     RECT  2.304 3.145 9.342 3.181 ;
     RECT  10.116 3.019 20.502 3.181 ;
     RECT  21.42 3.067 21.582 3.341 ;
     RECT  0.504 2.861 0.558 3.533 ;
     RECT  2.304 3.181 20.502 3.691 ;
     RECT  21.492 3.341 21.582 4.123 ;
     RECT  0.504 3.533 0.522 4.205 ;
     RECT  21.42 4.123 21.582 4.253 ;
     RECT  0.108 4.261 0.342 4.685 ;
     RECT  0.324 4.685 0.342 4.973 ;
     RECT  21.42 4.253 21.438 5.035 ;
     RECT  21.42 5.035 21.51 5.501 ;
     RECT  2.304 3.691 20.574 5.809 ;
     RECT  2.268 5.809 20.574 5.873 ;
     RECT  0.144 5.899 0.162 6.077 ;
     RECT  1.152 5.227 1.17 6.079 ;
     RECT  2.268 5.873 20.43 6.269 ;
     RECT  9.108 6.269 20.43 6.305 ;
     RECT  21.456 5.501 21.51 6.475 ;
     RECT  0.54 6.079 1.17 6.509 ;
     RECT  21.384 6.475 21.51 6.667 ;
     RECT  2.268 6.269 8.262 6.817 ;
     RECT  9.144 6.305 20.43 6.845 ;
     RECT  14.796 6.845 20.43 6.889 ;
     RECT  0.108 6.817 0.198 6.917 ;
     RECT  2.232 6.817 8.262 6.917 ;
     RECT  14.796 6.889 20.538 6.953 ;
     RECT  1.152 6.509 1.17 7.051 ;
     RECT  9.144 6.845 13.986 7.051 ;
     RECT  9.108 7.051 13.986 7.151 ;
     RECT  2.268 6.917 8.262 7.159 ;
     RECT  9.108 7.151 11.97 7.159 ;
     RECT  20.124 6.953 20.538 7.223 ;
     RECT  20.124 7.223 20.43 7.421 ;
     RECT  1.152 7.051 1.422 7.457 ;
     RECT  13.032 7.151 13.986 7.627 ;
     RECT  14.796 6.953 19.386 7.627 ;
     RECT  13.032 7.627 19.386 7.933 ;
     RECT  0.324 7.819 0.342 7.949 ;
     RECT  21.276 6.667 21.51 7.961 ;
     RECT  2.268 7.159 11.97 8.005 ;
     RECT  12.78 7.933 19.386 8.005 ;
     RECT  20.196 7.421 20.43 8.167 ;
     RECT  2.268 8.005 19.386 8.437 ;
     RECT  2.268 8.437 19.422 8.525 ;
     RECT  2.304 8.525 19.422 8.537 ;
     RECT  20.16 8.167 20.43 8.581 ;
     RECT  21.42 7.961 21.51 8.971 ;
     RECT  2.34 8.537 19.422 8.977 ;
     RECT  20.16 8.581 20.538 8.977 ;
     RECT  1.404 7.457 1.422 9.347 ;
     RECT  2.34 8.977 20.538 9.481 ;
     RECT  21.384 8.971 21.51 9.553 ;
     RECT  21.312 9.553 21.51 9.959 ;
     RECT  0.432 9.931 0.45 10.021 ;
     RECT  0.432 10.021 0.522 10.129 ;
     RECT  21.312 9.959 21.474 10.229 ;
     RECT  2.304 9.481 20.538 10.253 ;
     RECT  21.312 10.229 21.366 10.253 ;
     RECT  0.432 10.129 0.558 10.399 ;
     RECT  0.396 10.399 0.558 10.669 ;
     RECT  2.34 10.253 20.538 10.733 ;
     RECT  0.36 10.669 0.558 10.786 ;
     RECT  19.908 10.733 20.538 11.003 ;
     RECT  21.312 10.253 21.33 11.083 ;
     RECT  0.324 10.786 0.558 11.179 ;
     RECT  21.276 11.083 21.33 11.179 ;
     RECT  21.276 11.179 21.438 11.213 ;
     RECT  2.34 10.733 19.098 11.245 ;
     RECT  21.42 11.213 21.438 11.357 ;
     RECT  0.324 11.179 0.594 11.405 ;
     RECT  0.468 11.405 0.594 11.755 ;
     RECT  2.304 11.245 19.098 11.785 ;
     RECT  19.908 11.003 20.502 11.785 ;
     RECT  0.468 11.755 0.63 11.885 ;
     RECT  1.404 10.123 1.422 12.119 ;
     RECT  0.468 11.885 0.558 12.283 ;
     RECT  0.144 12.283 0.558 12.365 ;
     RECT  2.304 11.785 20.502 12.551 ;
     RECT  0.144 12.365 0.522 12.941 ;
     RECT  0.144 12.941 0.342 12.991 ;
     RECT  0.108 12.991 0.342 13.325 ;
     RECT  1.152 13.483 1.17 13.613 ;
     RECT  2.304 12.551 20.466 13.945 ;
     RECT  2.304 13.945 20.538 13.963 ;
     RECT  2.268 13.963 20.538 14.009 ;
     RECT  0.108 13.325 0.234 14.059 ;
     RECT  0.108 14.059 0.342 14.189 ;
     RECT  0.108 14.189 0.306 14.381 ;
     RECT  2.304 14.009 20.538 14.477 ;
     RECT  2.415 14.477 20.538 14.719 ;
     RECT  21.456 12.523 21.474 14.731 ;
     RECT  0.288 14.381 0.306 15.025 ;
     RECT  21.42 14.731 21.474 15.053 ;
     RECT  0.288 15.025 0.486 15.061 ;
     RECT  21.312 15.115 21.33 15.245 ;
     RECT  0.288 15.061 0.558 15.331 ;
     RECT  2.415 14.719 20.574 15.565 ;
     RECT  2.304 15.565 20.574 16.027 ;
     RECT  2.268 16.027 20.574 16.295 ;
     RECT  2.304 16.295 20.574 16.3 ;
     RECT  2.304 16.3 20.61 17.069 ;
     RECT  21.492 17.455 21.51 17.549 ;
     RECT  0.108 15.331 0.558 17.741 ;
     RECT  21.312 17.803 21.438 17.933 ;
     RECT  2.304 17.069 20.538 18.029 ;
     RECT  21.42 17.933 21.438 18.077 ;
     RECT  0.108 17.741 0.522 18.317 ;
     RECT  0.108 18.317 0.45 18.605 ;
     RECT  2.304 18.029 20.43 19.273 ;
     RECT  0.144 18.605 0.45 19.651 ;
     RECT  2.304 19.273 20.538 20.111 ;
     RECT  0.144 19.651 0.558 20.191 ;
     RECT  2.304 20.111 17.478 20.309 ;
     RECT  2.304 20.309 16.578 20.389 ;
     RECT  2.268 20.389 16.578 20.489 ;
     RECT  17.424 20.309 17.478 20.893 ;
     RECT  18.216 20.111 20.538 20.893 ;
     RECT  2.268 20.489 16.542 20.957 ;
     RECT  21.492 19.813 21.51 21.005 ;
     RECT  2.268 20.957 11.754 21.101 ;
     RECT  15.408 20.957 16.542 21.271 ;
     RECT  17.424 20.893 20.538 21.271 ;
     RECT  15.408 21.271 20.538 21.293 ;
     RECT  15.408 21.293 20.43 21.461 ;
     RECT  2.304 21.101 11.754 21.703 ;
     RECT  12.492 20.957 14.31 21.703 ;
     RECT  0.108 20.191 0.558 21.739 ;
     RECT  2.304 21.703 14.31 21.739 ;
     RECT  15.408 21.461 19.962 21.739 ;
     RECT  0.108 21.739 0.666 21.869 ;
     RECT  2.304 21.739 19.962 22.108 ;
     RECT  2.268 22.108 19.962 22.207 ;
     RECT  0.108 21.869 0.558 22.253 ;
     RECT  0.144 22.253 0.558 22.349 ;
     RECT  2.232 22.207 19.962 22.505 ;
     RECT  2.304 22.505 19.962 22.783 ;
     RECT  0.144 22.349 0.522 23.251 ;
     RECT  2.304 22.783 20.538 23.309 ;
     RECT  0.108 23.251 0.522 23.323 ;
     RECT  2.304 23.309 19.17 23.323 ;
     RECT  2.232 23.323 19.17 23.459 ;
     RECT  2.268 23.459 19.17 23.585 ;
     RECT  21.492 23.053 21.51 23.611 ;
     RECT  21.42 23.611 21.51 23.789 ;
     RECT  21.492 23.789 21.51 23.885 ;
     RECT  0.108 23.323 0.558 24.077 ;
     RECT  19.944 23.309 20.538 24.077 ;
     RECT  2.304 23.585 19.17 24.089 ;
     RECT  19.944 24.077 20.502 24.139 ;
     RECT  2.304 24.089 19.062 24.161 ;
     RECT  0.108 24.077 0.486 24.173 ;
     RECT  0.144 24.173 0.486 24.269 ;
     RECT  2.304 24.161 19.026 24.539 ;
     RECT  0.468 24.269 0.486 24.653 ;
     RECT  2.304 24.539 11.538 24.781 ;
     RECT  2.268 24.781 11.538 24.845 ;
     RECT  12.672 24.539 19.026 24.899 ;
     RECT  13.104 24.899 19.026 24.971 ;
     RECT  19.908 24.139 20.502 24.971 ;
     RECT  0.18 25.015 0.198 25.051 ;
     RECT  13.215 24.971 19.026 25.285 ;
     RECT  0.108 25.051 0.198 25.519 ;
     RECT  19.908 24.971 20.466 25.579 ;
     RECT  19.872 25.579 20.466 25.675 ;
     RECT  2.304 24.845 11.538 25.825 ;
     RECT  2.304 25.825 12.078 25.861 ;
     RECT  13.215 25.285 19.062 25.951 ;
     RECT  19.836 25.675 20.466 25.963 ;
     RECT  0.108 25.519 0.558 26.059 ;
     RECT  19.836 25.963 20.538 26.131 ;
     RECT  2.268 25.861 12.078 26.221 ;
     RECT  13.104 25.951 19.062 26.221 ;
     RECT  2.268 26.221 19.062 26.299 ;
     RECT  19.836 26.131 20.574 26.393 ;
     RECT  2.268 26.299 19.098 26.519 ;
     RECT  2.268 26.519 13.698 26.563 ;
     RECT  2.232 26.563 13.698 26.591 ;
     RECT  13.14 26.591 13.698 26.627 ;
     RECT  0.108 26.059 0.666 26.671 ;
     RECT  0.108 26.671 1.206 26.716 ;
     RECT  0.108 26.716 1.278 26.789 ;
     RECT  14.436 26.519 19.098 26.825 ;
     RECT  21.42 26.635 21.438 26.861 ;
     RECT  19.872 26.393 20.574 26.897 ;
     RECT  2.232 26.591 12.33 26.969 ;
     RECT  14.436 26.825 14.994 27.337 ;
     RECT  15.732 26.825 19.098 27.337 ;
     RECT  2.34 26.969 12.33 27.373 ;
     RECT  13.14 26.627 13.497 27.373 ;
     RECT  15.732 27.337 19.134 27.437 ;
     RECT  14.328 27.337 14.994 27.679 ;
     RECT  15.732 27.437 19.098 27.679 ;
     RECT  2.34 27.373 13.497 27.715 ;
     RECT  14.328 27.679 19.098 27.715 ;
     RECT  19.872 26.897 20.538 27.751 ;
     RECT  19.872 27.751 20.574 27.917 ;
     RECT  0.108 26.789 0.558 28.109 ;
     RECT  19.872 27.917 20.538 28.205 ;
     RECT  2.232 27.715 19.098 28.291 ;
     RECT  19.872 28.205 20.502 28.291 ;
     RECT  0.108 28.109 0.522 28.493 ;
     RECT  21.492 28.075 21.51 28.589 ;
     RECT  0.144 28.493 0.522 28.921 ;
     RECT  0.144 28.921 1.17 29.065 ;
     RECT  0.144 29.065 1.242 29.299 ;
     RECT  2.232 28.291 20.502 29.299 ;
     RECT  0.144 29.299 20.502 29.335 ;
     RECT  0.144 29.335 20.538 29.515 ;
     RECT  0.108 29.515 20.538 29.741 ;
     RECT  0.108 29.741 20.502 30.109 ;
     RECT  0.036 30.109 20.502 30.137 ;
     RECT  21.42 30.763 21.438 30.941 ;
     RECT  0.036 30.137 20.43 31.153 ;
     RECT  0.036 31.153 20.538 31.373 ;
     RECT  0.036 31.373 20.322 31.721 ;
     RECT  10.224 31.721 20.322 31.829 ;
     RECT  10.515 31.829 14.418 31.853 ;
     RECT  21.492 31.051 21.51 31.915 ;
     RECT  10.515 31.853 11.322 31.919 ;
     RECT  12.24 31.853 14.418 31.919 ;
     RECT  15.3 31.829 20.322 31.991 ;
     RECT  17.172 31.991 20.322 32.027 ;
     RECT  21.312 31.915 21.51 32.045 ;
     RECT  12.24 31.919 13.698 32.063 ;
     RECT  15.3 31.991 16.197 32.063 ;
     RECT  17.568 32.027 20.322 32.063 ;
     RECT  21.492 32.045 21.51 32.099 ;
     RECT  17.856 32.063 20.322 32.107 ;
     RECT  0.036 31.721 9.486 32.144 ;
     RECT  0.072 32.144 9.486 32.147 ;
     RECT  10.515 31.919 10.797 32.147 ;
     RECT  15.876 32.063 16.197 32.147 ;
     RECT  0.072 32.147 5.205 32.189 ;
     RECT  17.856 32.107 20.394 32.203 ;
     RECT  5.976 32.147 9.486 32.225 ;
     RECT  15.876 32.147 16.005 32.225 ;
     RECT  17.856 32.203 20.502 32.225 ;
     RECT  0.072 32.189 3.942 32.237 ;
     RECT  17.856 32.225 17.874 32.237 ;
     RECT  8.928 32.225 9.486 32.261 ;
     RECT  18.615 32.225 20.502 32.261 ;
     RECT  0.072 32.237 1.494 32.297 ;
     RECT  4.68 32.189 5.205 32.297 ;
     RECT  12.564 32.063 13.698 32.297 ;
     RECT  19.872 32.261 20.502 32.297 ;
     RECT  18.615 32.261 18.846 32.333 ;
     RECT  20.484 32.297 20.502 32.333 ;
     RECT  2.304 32.237 3.942 32.369 ;
     RECT  5.976 32.225 8.154 32.369 ;
     RECT  9.396 32.261 9.486 32.369 ;
     RECT  5.004 32.297 5.205 32.417 ;
     RECT  6.66 32.369 7.905 32.417 ;
     RECT  10.515 32.147 10.605 32.417 ;
     RECT  13.215 32.297 13.698 32.417 ;
     RECT  15.915 32.225 16.005 32.417 ;
     RECT  18.615 32.333 18.705 32.417 ;
     RECT  2.304 32.369 3.726 32.429 ;
     RECT  6.66 32.417 7.722 32.459 ;
     RECT  9.396 32.369 9.414 32.459 ;
     RECT  2.34 32.429 3.726 32.495 ;
     RECT  6.66 32.459 6.678 32.495 ;
     RECT  7.704 32.459 7.722 32.495 ;
     RECT  13.68 32.417 13.698 32.495 ;
     RECT  0.108 32.297 1.494 32.717 ;
     RECT  2.34 32.495 3.546 32.813 ;
     RECT  2.34 32.813 3.402 32.909 ;
     RECT  2.34 32.909 2.358 33.005 ;
     RECT  1.152 32.717 1.494 33.101 ;
     RECT  1.188 33.101 1.494 33.197 ;
     RECT  1.224 33.197 1.494 33.293 ;
     RECT  1.404 33.293 1.494 33.389 ;
     RECT  5.004 32.417 5.022 33.485 ;
     RECT  0.108 32.717 0.126 33.581 ;
     RECT  3.384 32.909 3.402 33.677 ;
     RECT  1.404 33.389 1.422 33.773 ;
    LAYER M4 ;
     RECT  0.06 10.032 0.533 33.768 ;
     RECT  0.533 15.744 0.569 33.768 ;
     RECT  0.569 28.272 1.433 33.768 ;
     RECT  0.06 2.352 2.257 8.424 ;
     RECT  0.569 15.744 2.401 27.144 ;
     RECT  1.433 28.272 2.401 33.672 ;
     RECT  2.257 2.352 2.408 8.52 ;
     RECT  0.533 10.032 2.408 14.568 ;
     RECT  2.401 15.744 2.408 33.672 ;
     RECT  2.408 2.148 2.512 33.672 ;
     RECT  2.512 2.418 2.704 33.672 ;
     RECT  2.704 10.416 3.413 33.672 ;
     RECT  2.704 2.592 3.485 9.384 ;
     RECT  3.413 10.416 3.557 33.48 ;
     RECT  3.485 4.656 3.629 9.384 ;
     RECT  3.557 10.416 3.733 32.184 ;
     RECT  3.485 2.592 4.025 3.672 ;
     RECT  3.629 4.656 4.025 8.52 ;
     RECT  3.733 10.128 4.993 32.184 ;
     RECT  3.557 33.456 5.033 33.48 ;
     RECT  4.025 2.784 5.108 3.672 ;
     RECT  4.025 4.848 5.108 8.232 ;
     RECT  4.993 9.792 5.108 32.184 ;
     RECT  5.108 2.148 5.212 32.412 ;
     RECT  5.212 2.418 5.404 32.142 ;
     RECT  5.404 2.496 5.537 31.752 ;
     RECT  5.537 2.496 5.861 7.704 ;
     RECT  5.861 2.496 6.541 7.416 ;
     RECT  5.537 8.688 6.829 31.752 ;
     RECT  6.541 2.4 7.189 7.416 ;
     RECT  6.829 8.544 7.189 31.752 ;
     RECT  7.189 2.4 7.669 31.752 ;
     RECT  7.669 2.4 7.693 31.8 ;
     RECT  7.693 2.4 7.801 31.992 ;
     RECT  7.801 2.4 7.808 32.04 ;
     RECT  7.808 2.148 7.912 32.412 ;
     RECT  7.912 2.418 8.104 32.142 ;
     RECT  8.104 2.496 8.243 32.04 ;
     RECT  8.243 2.496 8.561 31.992 ;
     RECT  8.561 2.496 8.597 31.896 ;
     RECT  8.597 2.496 8.669 24.552 ;
     RECT  8.669 2.496 8.849 17.448 ;
     RECT  8.669 18.576 9.029 24.552 ;
     RECT  8.597 25.68 9.317 31.896 ;
     RECT  9.029 18.672 9.533 24.552 ;
     RECT  8.849 2.496 9.889 17.4 ;
     RECT  9.889 2.496 10.508 17.688 ;
     RECT  9.533 18.672 10.508 24.456 ;
     RECT  9.317 25.68 10.508 31.8 ;
     RECT  10.508 2.148 10.612 32.412 ;
     RECT  10.612 2.418 10.804 32.142 ;
     RECT  10.804 21.936 11.027 24.504 ;
     RECT  10.804 2.496 11.045 20.376 ;
     RECT  11.045 19.248 11.117 20.376 ;
     RECT  10.804 25.728 11.699 31.848 ;
     RECT  11.027 21.936 12.085 24.456 ;
     RECT  12.085 21.888 12.197 24.456 ;
     RECT  11.699 31.392 12.229 31.848 ;
     RECT  11.117 19.248 12.337 20.184 ;
     RECT  12.197 21.984 12.517 24.456 ;
     RECT  11.699 25.728 12.517 30.168 ;
     RECT  12.517 21.984 12.697 30.168 ;
     RECT  11.045 2.496 12.901 18.216 ;
     RECT  12.697 21.984 13.021 30.216 ;
     RECT  12.229 31.392 13.021 31.944 ;
     RECT  12.901 1.728 13.025 18.216 ;
     RECT  13.025 2.148 13.165 18.216 ;
     RECT  12.337 19.248 13.165 20.328 ;
     RECT  13.165 2.148 13.208 20.328 ;
     RECT  13.021 21.984 13.208 31.944 ;
     RECT  13.208 2.148 13.312 32.412 ;
     RECT  13.312 2.418 13.504 32.142 ;
     RECT  13.504 30.864 13.565 31.944 ;
     RECT  13.504 25.776 13.745 29.64 ;
     RECT  13.504 21.984 13.853 24.504 ;
     RECT  13.504 2.496 13.907 20.328 ;
     RECT  13.907 2.496 14.285 20.088 ;
     RECT  13.853 21.984 14.285 24.456 ;
     RECT  14.285 21.984 14.357 23.928 ;
     RECT  14.357 21.984 14.465 22.584 ;
     RECT  13.745 25.968 14.785 29.64 ;
     RECT  14.285 2.496 15.289 18.84 ;
     RECT  14.285 19.824 15.289 20.088 ;
     RECT  14.785 25.584 15.317 29.64 ;
     RECT  13.565 31.152 15.397 31.944 ;
     RECT  15.289 2.496 15.493 20.088 ;
     RECT  15.317 25.056 15.649 29.64 ;
     RECT  15.397 30.672 15.649 31.944 ;
     RECT  14.357 23.568 15.901 23.928 ;
     RECT  15.649 25.056 15.901 31.944 ;
     RECT  15.493 2.496 15.908 20.616 ;
     RECT  14.465 22.032 15.908 22.584 ;
     RECT  15.901 23.568 15.908 31.944 ;
     RECT  15.908 2.148 16.012 32.412 ;
     RECT  16.012 2.418 16.204 32.142 ;
     RECT  16.204 22.032 16.229 31.944 ;
     RECT  16.229 22.56 16.625 31.944 ;
     RECT  16.625 22.56 17.737 31.896 ;
     RECT  17.737 22.56 17.809 32.04 ;
     RECT  17.809 21.792 17.845 32.04 ;
     RECT  17.845 21.792 18.373 32.232 ;
     RECT  16.204 2.448 18.493 18.84 ;
     RECT  18.493 2.448 18.565 19.368 ;
     RECT  18.565 2.256 18.608 19.368 ;
     RECT  18.373 21.648 18.608 32.232 ;
     RECT  18.608 2.148 18.712 32.412 ;
     RECT  18.712 2.148 18.904 32.232 ;
     RECT  18.904 22.32 19.001 23.64 ;
     RECT  18.904 2.148 19.177 20.136 ;
     RECT  19.177 1.488 19.357 20.136 ;
     RECT  19.001 22.992 19.897 23.64 ;
     RECT  18.904 25.488 19.897 32.232 ;
     RECT  19.357 0.72 19.933 20.136 ;
     RECT  18.904 21.168 19.933 21.192 ;
     RECT  19.897 22.992 21.491 32.232 ;
     RECT  19.933 0.72 21.564 21.384 ;
     RECT  21.491 22.992 21.564 32.136 ;
    LAYER M5 ;
     RECT  12.816 0.016 12.936 2.137 ;
     RECT  2.4 2.137 2.52 2.151 ;
     RECT  5.1 2.137 5.22 2.151 ;
     RECT  7.8 2.137 7.92 2.151 ;
     RECT  10.5 2.137 10.62 2.151 ;
     RECT  12.816 2.137 13.32 2.151 ;
     RECT  15.9 2.137 16.02 2.151 ;
     RECT  18.6 2.137 18.72 2.151 ;
     RECT  7.8 2.151 8.112 2.437 ;
     RECT  6.864 2.437 8.112 2.579 ;
     RECT  15.9 2.151 16.212 2.581 ;
     RECT  18.6 2.151 18.912 2.725 ;
     RECT  18.6 2.725 19.032 2.821 ;
     RECT  0.144 2.581 0.168 2.867 ;
     RECT  15.9 2.581 17.064 3.061 ;
     RECT  10.5 2.151 10.812 3.157 ;
     RECT  15.9 3.061 17.592 3.349 ;
     RECT  18.6 2.821 19.32 3.349 ;
     RECT  15.9 3.349 19.32 3.397 ;
     RECT  7.8 2.579 8.112 3.877 ;
     RECT  15.9 3.397 19.368 3.877 ;
     RECT  15.792 3.877 19.368 4.115 ;
     RECT  10.224 3.157 10.812 4.595 ;
     RECT  15.792 4.115 16.212 4.595 ;
     RECT  17.424 4.115 19.368 4.595 ;
     RECT  12.816 2.151 13.512 5.029 ;
     RECT  0.144 4.933 0.168 5.123 ;
     RECT  10.5 4.595 10.812 5.365 ;
     RECT  6.816 3.877 8.112 5.557 ;
     RECT  6.816 5.557 9.096 5.747 ;
     RECT  17.424 4.595 19.32 5.747 ;
     RECT  5.1 2.151 5.412 6.229 ;
     RECT  17.568 5.747 19.32 6.565 ;
     RECT  7.536 5.747 9.096 6.659 ;
     RECT  17.568 6.565 19.368 6.899 ;
     RECT  5.1 6.229 6.216 7.285 ;
     RECT  5.1 7.285 6.648 7.331 ;
     RECT  15.9 4.595 16.212 7.765 ;
     RECT  10.5 5.365 11.016 7.909 ;
     RECT  0.144 7.765 0.168 7.955 ;
     RECT  6.624 7.331 6.648 8.197 ;
     RECT  7.8 6.659 9.096 8.197 ;
     RECT  6.624 8.197 9.096 8.533 ;
     RECT  18.144 6.899 19.368 8.627 ;
     RECT  6.624 8.533 9.144 8.771 ;
     RECT  10.368 7.909 11.016 8.819 ;
     RECT  6.624 8.771 9.096 9.011 ;
     RECT  18.432 8.627 19.368 9.155 ;
     RECT  7.008 9.011 9.096 9.203 ;
     RECT  10.368 8.819 10.812 9.301 ;
     RECT  5.1 7.331 5.412 9.541 ;
     RECT  18.432 9.155 19.08 9.637 ;
     RECT  12.816 5.029 14.424 10.309 ;
     RECT  15.792 7.765 16.212 10.309 ;
     RECT  12.72 10.309 14.424 10.355 ;
     RECT  7.104 9.203 9.096 10.453 ;
     RECT  18.24 9.637 19.08 10.501 ;
     RECT  15.792 10.309 16.392 10.643 ;
     RECT  7.104 10.453 9.192 10.739 ;
     RECT  15.792 10.643 16.212 10.789 ;
     RECT  12.72 10.355 13.848 10.883 ;
     RECT  7.104 10.739 8.568 10.931 ;
     RECT  10.32 9.301 10.812 11.125 ;
     RECT  5.1 9.541 5.88 11.219 ;
     RECT  7.104 10.931 8.328 11.267 ;
     RECT  12.72 10.883 13.704 11.365 ;
     RECT  12 11.365 13.704 11.411 ;
     RECT  17.616 10.501 19.08 11.459 ;
     RECT  18.048 11.459 19.08 11.749 ;
     RECT  12 11.411 13.512 12.035 ;
     RECT  14.976 10.789 16.212 12.467 ;
     RECT  7.104 11.267 8.232 12.517 ;
     RECT  7.008 12.517 8.232 12.563 ;
     RECT  18.048 11.749 19.368 12.563 ;
     RECT  15.9 12.467 16.212 12.565 ;
     RECT  15.9 12.565 16.92 12.803 ;
     RECT  18.048 12.563 19.08 12.997 ;
     RECT  10.272 11.125 10.812 13.045 ;
     RECT  12.144 12.035 13.512 13.045 ;
     RECT  10.272 13.045 13.512 13.187 ;
     RECT  7.008 12.563 8.112 13.283 ;
     RECT  17.808 12.997 19.08 14.149 ;
     RECT  0.144 13.141 0.168 14.195 ;
     RECT  2.4 2.151 2.712 14.389 ;
     RECT  2.304 14.389 2.712 14.579 ;
     RECT  5.1 11.219 5.688 14.675 ;
     RECT  17.808 14.149 19.368 15.205 ;
     RECT  12.144 13.187 13.512 15.301 ;
     RECT  21.408 15.205 21.432 15.395 ;
     RECT  15.9 12.803 16.212 15.397 ;
     RECT  15.168 15.397 16.212 16.019 ;
     RECT  12.144 15.301 13.608 16.067 ;
     RECT  15.9 16.019 16.212 16.405 ;
     RECT  17.616 15.205 19.368 16.405 ;
     RECT  15.9 16.405 19.368 16.547 ;
     RECT  17.616 16.547 19.368 16.595 ;
     RECT  18.096 16.595 19.368 16.643 ;
     RECT  18.096 16.643 19.128 16.883 ;
     RECT  7.104 13.283 8.112 17.029 ;
     RECT  12.144 16.067 13.512 17.077 ;
     RECT  5.1 14.675 5.592 17.171 ;
     RECT  18.096 16.883 19.08 17.267 ;
     RECT  18.192 17.267 19.08 17.411 ;
     RECT  12.144 17.077 13.992 17.555 ;
     RECT  15.9 16.547 16.212 17.557 ;
     RECT  12.192 17.555 13.992 17.605 ;
     RECT  12.192 17.605 14.568 18.179 ;
     RECT  7.008 17.029 8.112 18.181 ;
     RECT  18.192 17.411 19.032 18.275 ;
     RECT  14.544 18.179 14.568 18.851 ;
     RECT  18.192 18.275 18.912 18.851 ;
     RECT  12.192 18.179 13.512 19.333 ;
     RECT  15.744 17.557 16.212 19.381 ;
     RECT  6.912 18.181 8.112 20.005 ;
     RECT  12.192 19.333 13.896 20.101 ;
     RECT  6.912 20.005 8.52 20.195 ;
     RECT  12.096 20.101 13.896 20.339 ;
     RECT  6.912 20.195 8.424 20.387 ;
     RECT  10.272 13.187 10.812 20.675 ;
     RECT  10.32 20.675 10.812 21.155 ;
     RECT  18.6 18.851 18.912 21.637 ;
     RECT  12.096 20.339 13.512 21.923 ;
     RECT  15.504 19.381 16.212 22.259 ;
     RECT  6.912 20.387 8.328 22.261 ;
     RECT  6.912 22.261 8.808 22.405 ;
     RECT  10.5 21.155 10.812 22.453 ;
     RECT  6.864 22.405 8.808 22.547 ;
     RECT  6.912 22.547 8.808 22.595 ;
     RECT  10.5 22.453 10.92 22.691 ;
     RECT  12.192 21.923 13.512 22.835 ;
     RECT  12.384 22.835 13.512 23.459 ;
     RECT  18.384 21.637 18.912 23.603 ;
     RECT  18.48 23.603 18.912 23.651 ;
     RECT  0.144 24.181 0.168 24.467 ;
     RECT  10.5 22.691 10.812 24.469 ;
     RECT  12.528 23.459 13.512 24.469 ;
     RECT  6.912 22.595 8.328 24.517 ;
     RECT  15.9 22.259 16.212 25.045 ;
     RECT  15.36 25.045 16.212 25.619 ;
     RECT  6.912 24.517 8.568 25.669 ;
     RECT  12.528 24.469 13.704 26.051 ;
     RECT  10.5 24.469 11.016 26.243 ;
     RECT  15.9 25.619 16.212 26.245 ;
     RECT  6.912 25.669 8.952 26.291 ;
     RECT  7.536 26.291 8.952 26.579 ;
     RECT  15.9 26.245 16.872 26.675 ;
     RECT  14.832 26.533 14.856 26.723 ;
     RECT  2.4 14.579 2.712 27.013 ;
     RECT  10.5 26.243 10.812 27.205 ;
     RECT  10.5 27.205 10.968 27.733 ;
     RECT  12.528 26.051 13.512 27.733 ;
     RECT  15.9 26.675 16.212 27.925 ;
     RECT  15.9 27.925 17.16 28.067 ;
     RECT  10.5 27.733 13.512 28.501 ;
     RECT  10.5 28.501 13.8 28.691 ;
     RECT  12.72 28.691 13.8 28.739 ;
     RECT  10.5 28.691 11.688 28.837 ;
     RECT  7.536 26.579 8.328 29.077 ;
     RECT  7.536 29.077 8.952 29.125 ;
     RECT  14.832 27.877 14.856 29.219 ;
     RECT  12.72 28.739 13.512 29.267 ;
     RECT  2.4 27.013 2.808 29.411 ;
     RECT  5.1 17.171 5.412 29.413 ;
     RECT  7.536 29.125 9.288 29.555 ;
     RECT  5.1 29.413 5.736 29.651 ;
     RECT  7.536 29.555 8.952 29.891 ;
     RECT  15.9 28.067 16.212 30.373 ;
     RECT  10.368 28.837 11.688 30.565 ;
     RECT  5.1 29.651 5.688 30.803 ;
     RECT  7.536 29.891 8.328 30.851 ;
     RECT  0.288 30.757 0.312 30.899 ;
     RECT  7.68 30.851 8.328 31.475 ;
     RECT  10.272 30.565 11.688 31.523 ;
     RECT  1.152 31.429 1.176 31.619 ;
     RECT  10.5 31.523 11.688 31.669 ;
     RECT  7.68 31.475 8.232 31.811 ;
     RECT  10.5 31.669 11.736 31.859 ;
     RECT  15.9 30.373 16.344 31.955 ;
     RECT  7.8 31.811 8.232 32.051 ;
     RECT  21.456 32.005 21.48 32.243 ;
     RECT  2.4 29.411 2.712 32.409 ;
     RECT  5.1 30.803 5.412 32.409 ;
     RECT  7.8 32.051 8.112 32.409 ;
     RECT  10.5 31.859 10.812 32.409 ;
     RECT  13.2 29.267 13.512 32.409 ;
     RECT  15.9 31.955 16.212 32.409 ;
     RECT  18.6 23.651 18.912 32.409 ;
     RECT  2.4 32.409 2.52 32.423 ;
     RECT  5.1 32.409 5.22 32.423 ;
     RECT  7.8 32.409 7.92 32.423 ;
     RECT  10.5 32.409 10.62 32.423 ;
     RECT  13.2 32.409 13.32 32.423 ;
     RECT  15.9 32.409 16.02 32.423 ;
     RECT  18.6 32.409 18.72 32.423 ;
     RECT  5.412 2.437 6.864 2.579 ;
     RECT  5.412 2.579 7.8 3.877 ;
     RECT  17.592 3.061 18.6 3.349 ;
     RECT  5.412 3.877 6.816 5.747 ;
     RECT  16.212 4.115 17.424 5.747 ;
     RECT  10.224 4.595 10.5 5.557 ;
     RECT  15.792 4.595 15.9 5.029 ;
     RECT  14.424 5.029 15.9 7.765 ;
     RECT  9.096 5.557 10.5 7.909 ;
     RECT  5.412 5.747 7.536 6.229 ;
     RECT  16.212 5.747 17.568 6.899 ;
     RECT  6.216 6.229 7.536 6.659 ;
     RECT  6.216 6.659 7.8 7.285 ;
     RECT  6.648 7.285 7.8 8.197 ;
     RECT  5.412 7.331 6.624 9.011 ;
     RECT  14.424 7.765 15.792 10.355 ;
     RECT  9.096 7.909 10.368 8.533 ;
     RECT  9.144 8.533 10.368 8.771 ;
     RECT  18.24 8.627 18.432 9.637 ;
     RECT  9.096 8.771 10.368 9.301 ;
     RECT  5.412 9.011 7.008 9.203 ;
     RECT  5.412 9.203 7.104 9.541 ;
     RECT  9.096 9.301 10.32 10.453 ;
     RECT  5.88 9.541 7.104 11.219 ;
     RECT  13.848 10.355 15.792 10.789 ;
     RECT  9.192 10.453 10.32 10.739 ;
     RECT  16.392 10.501 17.616 10.643 ;
     RECT  16.212 10.643 17.616 11.459 ;
     RECT  10.272 10.739 10.32 11.125 ;
     RECT  13.848 10.789 14.976 10.883 ;
     RECT  13.704 10.883 14.976 11.411 ;
     RECT  5.688 11.219 7.104 12.517 ;
     RECT  10.812 11.365 12 12.035 ;
     RECT  13.512 11.411 14.976 12.467 ;
     RECT  16.212 11.459 18.048 12.565 ;
     RECT  10.812 12.035 12.144 13.045 ;
     RECT  5.688 12.517 7.008 13.283 ;
     RECT  16.92 12.565 18.048 12.803 ;
     RECT  17.808 12.803 18.048 12.997 ;
     RECT  10.812 13.187 12.144 17.555 ;
     RECT  5.688 13.283 7.104 14.675 ;
     RECT  5.592 14.675 7.104 17.029 ;
     RECT  16.212 15.205 17.616 16.405 ;
     RECT  13.512 16.067 13.608 17.077 ;
     RECT  16.212 16.547 17.616 16.595 ;
     RECT  5.592 17.029 7.008 17.171 ;
     RECT  5.412 17.171 7.008 18.181 ;
     RECT  10.812 17.555 12.192 20.101 ;
     RECT  14.568 17.605 15.744 18.851 ;
     RECT  13.512 18.179 14.544 18.851 ;
     RECT  5.412 18.181 6.912 22.405 ;
     RECT  13.512 18.851 13.896 19.333 ;
     RECT  15.504 18.851 15.744 19.381 ;
     RECT  10.812 20.101 12.096 21.923 ;
     RECT  10.812 21.923 12.192 22.453 ;
     RECT  5.412 22.405 6.864 22.547 ;
     RECT  10.92 22.453 12.192 22.691 ;
     RECT  5.412 22.547 6.912 26.291 ;
     RECT  10.812 22.691 12.192 22.835 ;
     RECT  12.384 23.459 12.528 24.469 ;
     RECT  11.016 24.469 12.528 26.243 ;
     RECT  15.36 25.619 15.9 26.533 ;
     RECT  13.512 26.051 13.704 26.533 ;
     RECT  10.812 26.243 12.528 27.205 ;
     RECT  13.512 26.533 14.832 26.723 ;
     RECT  14.856 26.533 15.9 26.723 ;
     RECT  16.212 26.675 16.872 27.925 ;
     RECT  13.512 26.723 15.9 27.877 ;
     RECT  10.968 27.205 12.528 27.733 ;
     RECT  13.512 27.877 14.832 28.501 ;
     RECT  14.856 27.877 15.9 29.219 ;
     RECT  17.16 27.925 18.6 28.067 ;
     RECT  13.8 28.501 14.832 28.739 ;
     RECT  11.688 28.691 12.72 29.267 ;
     RECT  13.512 28.739 14.832 29.219 ;
     RECT  8.952 29.077 10.368 29.125 ;
     RECT  9.288 29.125 10.368 29.555 ;
     RECT  11.688 29.267 13.2 31.669 ;
     RECT  8.952 29.555 10.368 29.891 ;
     RECT  10.272 29.891 10.368 30.565 ;
     RECT  1.176 31.429 2.4 31.619 ;
     RECT  11.736 31.669 13.2 31.859 ;
  END
END hbfd_rly_304_EW
END LIBRARY
